##
## LEF for PtnCells ;
## created by Innovus v19.12-s087_1 on Tue Apr 28 21:20:15 2026
##

VERSION 5.8 ;

BUSBITCHARS "[]" ;
DIVIDERCHAR "/" ;

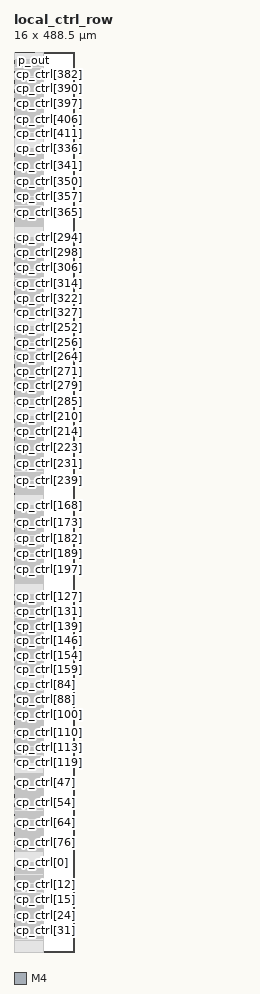
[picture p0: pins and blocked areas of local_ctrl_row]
MACRO local_ctrl_row
  CLASS BLOCK ;
  SIZE 16.000000 BY 488.500000 ;
  FOREIGN local_ctrl_row 0.000000 0.000000 ;
  ORIGIN 0 0 ;
  SYMMETRY X Y R90 ;
  PIN clk
    DIRECTION INPUT ;
    USE SIGNAL ;
    PORT
      LAYER M4 ;
        RECT 0.900000 488.300000 1.100000 488.500000 ;
    END
  END clk
  PIN rstn
    DIRECTION INPUT ;
    USE SIGNAL ;
    PORT
      LAYER M4 ;
        RECT 2.000000 488.300000 2.200000 488.500000 ;
    END
  END rstn
  PIN wr_vld
    DIRECTION INPUT ;
    USE SIGNAL ;
    PORT
      LAYER M4 ;
        RECT 4.200000 488.300000 4.400000 488.500000 ;
    END
  END wr_vld
  PIN wr_data_in
    DIRECTION INPUT ;
    USE SIGNAL ;
    PORT
      LAYER M4 ;
        RECT 3.100000 488.300000 3.300000 488.500000 ;
    END
  END wr_data_in
  PIN rd_rdy
    DIRECTION INPUT ;
    USE SIGNAL ;
    PORT
      LAYER M4 ;
        RECT 5.300000 488.300000 5.500000 488.500000 ;
    END
  END rd_rdy
  PIN p_code_vld
    DIRECTION INPUT ;
    USE SIGNAL ;
    PORT
      LAYER M4 ;
        RECT 8.600000 488.300000 8.800000 488.500000 ;
    END
  END p_code_vld
  PIN p_code[19]
    DIRECTION INPUT ;
    USE SIGNAL ;
    PORT
      LAYER M4 ;
        RECT 0.000000 449.120000 0.200000 449.320000 ;
    END
  END p_code[19]
  PIN p_code[18]
    DIRECTION INPUT ;
    USE SIGNAL ;
    PORT
      LAYER M4 ;
        RECT 0.000000 450.100000 0.200000 450.300000 ;
    END
  END p_code[18]
  PIN p_code[17]
    DIRECTION INPUT ;
    USE SIGNAL ;
    PORT
      LAYER M4 ;
        RECT 0.000000 400.670000 0.200000 400.870000 ;
    END
  END p_code[17]
  PIN p_code[16]
    DIRECTION INPUT ;
    USE SIGNAL ;
    PORT
      LAYER M4 ;
        RECT 0.000000 401.650000 0.200000 401.850000 ;
    END
  END p_code[16]
  PIN p_code[15]
    DIRECTION INPUT ;
    USE SIGNAL ;
    PORT
      LAYER M4 ;
        RECT 0.000000 352.220000 0.200000 352.420000 ;
    END
  END p_code[15]
  PIN p_code[14]
    DIRECTION INPUT ;
    USE SIGNAL ;
    PORT
      LAYER M4 ;
        RECT 0.000000 353.200000 0.200000 353.400000 ;
    END
  END p_code[14]
  PIN p_code[13]
    DIRECTION INPUT ;
    USE SIGNAL ;
    PORT
      LAYER M4 ;
        RECT 0.000000 303.770000 0.200000 303.970000 ;
    END
  END p_code[13]
  PIN p_code[12]
    DIRECTION INPUT ;
    USE SIGNAL ;
    PORT
      LAYER M4 ;
        RECT 0.000000 304.750000 0.200000 304.950000 ;
    END
  END p_code[12]
  PIN p_code[11]
    DIRECTION INPUT ;
    USE SIGNAL ;
    PORT
      LAYER M4 ;
        RECT 0.000000 255.320000 0.200000 255.520000 ;
    END
  END p_code[11]
  PIN p_code[10]
    DIRECTION INPUT ;
    USE SIGNAL ;
    PORT
      LAYER M4 ;
        RECT 0.000000 256.300000 0.200000 256.500000 ;
    END
  END p_code[10]
  PIN p_code[9]
    DIRECTION INPUT ;
    USE SIGNAL ;
    PORT
      LAYER M4 ;
        RECT 0.000000 206.870000 0.200000 207.070000 ;
    END
  END p_code[9]
  PIN p_code[8]
    DIRECTION INPUT ;
    USE SIGNAL ;
    PORT
      LAYER M4 ;
        RECT 0.000000 207.850000 0.200000 208.050000 ;
    END
  END p_code[8]
  PIN p_code[7]
    DIRECTION INPUT ;
    USE SIGNAL ;
    PORT
      LAYER M4 ;
        RECT 0.000000 158.420000 0.200000 158.620000 ;
    END
  END p_code[7]
  PIN p_code[6]
    DIRECTION INPUT ;
    USE SIGNAL ;
    PORT
      LAYER M4 ;
        RECT 0.000000 159.400000 0.200000 159.600000 ;
    END
  END p_code[6]
  PIN p_code[5]
    DIRECTION INPUT ;
    USE SIGNAL ;
    PORT
      LAYER M4 ;
        RECT 0.000000 109.970000 0.200000 110.170000 ;
    END
  END p_code[5]
  PIN p_code[4]
    DIRECTION INPUT ;
    USE SIGNAL ;
    PORT
      LAYER M4 ;
        RECT 0.000000 110.950000 0.200000 111.150000 ;
    END
  END p_code[4]
  PIN p_code[3]
    DIRECTION INPUT ;
    USE SIGNAL ;
    PORT
      LAYER M4 ;
        RECT 0.000000 61.520000 0.200000 61.720000 ;
    END
  END p_code[3]
  PIN p_code[2]
    DIRECTION INPUT ;
    USE SIGNAL ;
    PORT
      LAYER M4 ;
        RECT 0.000000 62.500000 0.200000 62.700000 ;
    END
  END p_code[2]
  PIN p_code[1]
    DIRECTION INPUT ;
    USE SIGNAL ;
    PORT
      LAYER M4 ;
        RECT 0.000000 13.070000 0.200000 13.270000 ;
    END
  END p_code[1]
  PIN p_code[0]
    DIRECTION INPUT ;
    USE SIGNAL ;
    PORT
      LAYER M4 ;
        RECT 0.000000 14.050000 0.200000 14.250000 ;
    END
  END p_code[0]
  PIN cp_ctrl[419]
    DIRECTION OUTPUT ;
    USE SIGNAL ;
    PORT
      LAYER M4 ;
        RECT 0.000000 455.000000 0.200000 455.200000 ;
    END
  END cp_ctrl[419]
  PIN cp_ctrl[418]
    DIRECTION OUTPUT ;
    USE SIGNAL ;
    PORT
      LAYER M4 ;
        RECT 0.000000 469.700000 0.200000 469.900000 ;
    END
  END cp_ctrl[418]
  PIN cp_ctrl[417]
    DIRECTION OUTPUT ;
    USE SIGNAL ;
    PORT
      LAYER M4 ;
        RECT 0.000000 442.260000 0.200000 442.460000 ;
    END
  END cp_ctrl[417]
  PIN cp_ctrl[416]
    DIRECTION OUTPUT ;
    USE SIGNAL ;
    PORT
      LAYER M4 ;
        RECT 0.000000 443.240000 0.200000 443.440000 ;
    END
  END cp_ctrl[416]
  PIN cp_ctrl[415]
    DIRECTION OUTPUT ;
    USE SIGNAL ;
    PORT
      LAYER M4 ;
        RECT 0.000000 444.220000 0.200000 444.420000 ;
    END
  END cp_ctrl[415]
  PIN cp_ctrl[414]
    DIRECTION OUTPUT ;
    USE SIGNAL ;
    PORT
      LAYER M4 ;
        RECT 0.000000 445.200000 0.200000 445.400000 ;
    END
  END cp_ctrl[414]
  PIN cp_ctrl[413]
    DIRECTION OUTPUT ;
    USE SIGNAL ;
    PORT
      LAYER M4 ;
        RECT 0.000000 446.180000 0.200000 446.380000 ;
    END
  END cp_ctrl[413]
  PIN cp_ctrl[412]
    DIRECTION OUTPUT ;
    USE SIGNAL ;
    PORT
      LAYER M4 ;
        RECT 0.000000 447.160000 0.200000 447.360000 ;
    END
  END cp_ctrl[412]
  PIN cp_ctrl[411]
    DIRECTION OUTPUT ;
    USE SIGNAL ;
    PORT
      LAYER M4 ;
        RECT 0.000000 448.140000 0.200000 448.340000 ;
    END
  END cp_ctrl[411]
  PIN cp_ctrl[410]
    DIRECTION OUTPUT ;
    USE SIGNAL ;
    PORT
      LAYER M4 ;
        RECT 0.000000 451.080000 0.200000 451.280000 ;
    END
  END cp_ctrl[410]
  PIN cp_ctrl[409]
    DIRECTION OUTPUT ;
    USE SIGNAL ;
    PORT
      LAYER M4 ;
        RECT 0.000000 452.060000 0.200000 452.260000 ;
    END
  END cp_ctrl[409]
  PIN cp_ctrl[408]
    DIRECTION OUTPUT ;
    USE SIGNAL ;
    PORT
      LAYER M4 ;
        RECT 0.000000 453.040000 0.200000 453.240000 ;
    END
  END cp_ctrl[408]
  PIN cp_ctrl[407]
    DIRECTION OUTPUT ;
    USE SIGNAL ;
    PORT
      LAYER M4 ;
        RECT 0.000000 454.020000 0.200000 454.220000 ;
    END
  END cp_ctrl[407]
  PIN cp_ctrl[406]
    DIRECTION OUTPUT ;
    USE SIGNAL ;
    PORT
      LAYER M4 ;
        RECT 0.000000 455.980000 0.200000 456.180000 ;
    END
  END cp_ctrl[406]
  PIN cp_ctrl[405]
    DIRECTION OUTPUT ;
    USE SIGNAL ;
    PORT
      LAYER M4 ;
        RECT 0.000000 456.960000 0.200000 457.160000 ;
    END
  END cp_ctrl[405]
  PIN cp_ctrl[404]
    DIRECTION OUTPUT ;
    USE SIGNAL ;
    PORT
      LAYER M4 ;
        RECT 0.000000 457.940000 0.200000 458.140000 ;
    END
  END cp_ctrl[404]
  PIN cp_ctrl[403]
    DIRECTION OUTPUT ;
    USE SIGNAL ;
    PORT
      LAYER M4 ;
        RECT 0.000000 458.920000 0.200000 459.120000 ;
    END
  END cp_ctrl[403]
  PIN cp_ctrl[402]
    DIRECTION OUTPUT ;
    USE SIGNAL ;
    PORT
      LAYER M4 ;
        RECT 0.000000 459.900000 0.200000 460.100000 ;
    END
  END cp_ctrl[402]
  PIN cp_ctrl[401]
    DIRECTION OUTPUT ;
    USE SIGNAL ;
    PORT
      LAYER M4 ;
        RECT 0.000000 460.880000 0.200000 461.080000 ;
    END
  END cp_ctrl[401]
  PIN cp_ctrl[400]
    DIRECTION OUTPUT ;
    USE SIGNAL ;
    PORT
      LAYER M4 ;
        RECT 0.000000 461.860000 0.200000 462.060000 ;
    END
  END cp_ctrl[400]
  PIN cp_ctrl[399]
    DIRECTION OUTPUT ;
    USE SIGNAL ;
    PORT
      LAYER M4 ;
        RECT 0.000000 462.840000 0.200000 463.040000 ;
    END
  END cp_ctrl[399]
  PIN cp_ctrl[398]
    DIRECTION OUTPUT ;
    USE SIGNAL ;
    PORT
      LAYER M4 ;
        RECT 0.000000 463.820000 0.200000 464.020000 ;
    END
  END cp_ctrl[398]
  PIN cp_ctrl[397]
    DIRECTION OUTPUT ;
    USE SIGNAL ;
    PORT
      LAYER M4 ;
        RECT 0.000000 464.800000 0.200000 465.000000 ;
    END
  END cp_ctrl[397]
  PIN cp_ctrl[396]
    DIRECTION OUTPUT ;
    USE SIGNAL ;
    PORT
      LAYER M4 ;
        RECT 0.000000 465.780000 0.200000 465.980000 ;
    END
  END cp_ctrl[396]
  PIN cp_ctrl[395]
    DIRECTION OUTPUT ;
    USE SIGNAL ;
    PORT
      LAYER M4 ;
        RECT 0.000000 466.760000 0.200000 466.960000 ;
    END
  END cp_ctrl[395]
  PIN cp_ctrl[394]
    DIRECTION OUTPUT ;
    USE SIGNAL ;
    PORT
      LAYER M4 ;
        RECT 0.000000 467.740000 0.200000 467.940000 ;
    END
  END cp_ctrl[394]
  PIN cp_ctrl[393]
    DIRECTION OUTPUT ;
    USE SIGNAL ;
    PORT
      LAYER M4 ;
        RECT 0.000000 468.720000 0.200000 468.920000 ;
    END
  END cp_ctrl[393]
  PIN cp_ctrl[392]
    DIRECTION OUTPUT ;
    USE SIGNAL ;
    PORT
      LAYER M4 ;
        RECT 0.000000 470.680000 0.200000 470.880000 ;
    END
  END cp_ctrl[392]
  PIN cp_ctrl[391]
    DIRECTION OUTPUT ;
    USE SIGNAL ;
    PORT
      LAYER M4 ;
        RECT 0.000000 471.660000 0.200000 471.860000 ;
    END
  END cp_ctrl[391]
  PIN cp_ctrl[390]
    DIRECTION OUTPUT ;
    USE SIGNAL ;
    PORT
      LAYER M4 ;
        RECT 0.000000 472.640000 0.200000 472.840000 ;
    END
  END cp_ctrl[390]
  PIN cp_ctrl[389]
    DIRECTION OUTPUT ;
    USE SIGNAL ;
    PORT
      LAYER M4 ;
        RECT 0.000000 473.620000 0.200000 473.820000 ;
    END
  END cp_ctrl[389]
  PIN cp_ctrl[388]
    DIRECTION OUTPUT ;
    USE SIGNAL ;
    PORT
      LAYER M4 ;
        RECT 0.000000 474.600000 0.200000 474.800000 ;
    END
  END cp_ctrl[388]
  PIN cp_ctrl[387]
    DIRECTION OUTPUT ;
    USE SIGNAL ;
    PORT
      LAYER M4 ;
        RECT 0.000000 475.580000 0.200000 475.780000 ;
    END
  END cp_ctrl[387]
  PIN cp_ctrl[386]
    DIRECTION OUTPUT ;
    USE SIGNAL ;
    PORT
      LAYER M4 ;
        RECT 0.000000 476.560000 0.200000 476.760000 ;
    END
  END cp_ctrl[386]
  PIN cp_ctrl[385]
    DIRECTION OUTPUT ;
    USE SIGNAL ;
    PORT
      LAYER M4 ;
        RECT 0.000000 477.540000 0.200000 477.740000 ;
    END
  END cp_ctrl[385]
  PIN cp_ctrl[384]
    DIRECTION OUTPUT ;
    USE SIGNAL ;
    PORT
      LAYER M4 ;
        RECT 0.000000 478.520000 0.200000 478.720000 ;
    END
  END cp_ctrl[384]
  PIN cp_ctrl[383]
    DIRECTION OUTPUT ;
    USE SIGNAL ;
    PORT
      LAYER M4 ;
        RECT 0.000000 479.500000 0.200000 479.700000 ;
    END
  END cp_ctrl[383]
  PIN cp_ctrl[382]
    DIRECTION OUTPUT ;
    USE SIGNAL ;
    PORT
      LAYER M4 ;
        RECT 0.000000 480.480000 0.200000 480.680000 ;
    END
  END cp_ctrl[382]
  PIN cp_ctrl[381]
    DIRECTION OUTPUT ;
    USE SIGNAL ;
    PORT
      LAYER M4 ;
        RECT 0.000000 481.460000 0.200000 481.660000 ;
    END
  END cp_ctrl[381]
  PIN cp_ctrl[380]
    DIRECTION OUTPUT ;
    USE SIGNAL ;
    PORT
      LAYER M4 ;
        RECT 0.000000 482.440000 0.200000 482.640000 ;
    END
  END cp_ctrl[380]
  PIN cp_ctrl[379]
    DIRECTION OUTPUT ;
    USE SIGNAL ;
    PORT
      LAYER M4 ;
        RECT 0.000000 483.420000 0.200000 483.620000 ;
    END
  END cp_ctrl[379]
  PIN cp_ctrl[378]
    DIRECTION OUTPUT ;
    USE SIGNAL ;
    PORT
      LAYER M4 ;
        RECT 0.000000 484.400000 0.200000 484.600000 ;
    END
  END cp_ctrl[378]
  PIN cp_ctrl[377]
    DIRECTION OUTPUT ;
    USE SIGNAL ;
    PORT
      LAYER M4 ;
        RECT 0.000000 406.550000 0.200000 406.750000 ;
    END
  END cp_ctrl[377]
  PIN cp_ctrl[376]
    DIRECTION OUTPUT ;
    USE SIGNAL ;
    PORT
      LAYER M4 ;
        RECT 0.000000 421.250000 0.200000 421.450000 ;
    END
  END cp_ctrl[376]
  PIN cp_ctrl[375]
    DIRECTION OUTPUT ;
    USE SIGNAL ;
    PORT
      LAYER M4 ;
        RECT 0.000000 393.810000 0.200000 394.010000 ;
    END
  END cp_ctrl[375]
  PIN cp_ctrl[374]
    DIRECTION OUTPUT ;
    USE SIGNAL ;
    PORT
      LAYER M4 ;
        RECT 0.000000 394.790000 0.200000 394.990000 ;
    END
  END cp_ctrl[374]
  PIN cp_ctrl[373]
    DIRECTION OUTPUT ;
    USE SIGNAL ;
    PORT
      LAYER M4 ;
        RECT 0.000000 395.770000 0.200000 395.970000 ;
    END
  END cp_ctrl[373]
  PIN cp_ctrl[372]
    DIRECTION OUTPUT ;
    USE SIGNAL ;
    PORT
      LAYER M4 ;
        RECT 0.000000 396.750000 0.200000 396.950000 ;
    END
  END cp_ctrl[372]
  PIN cp_ctrl[371]
    DIRECTION OUTPUT ;
    USE SIGNAL ;
    PORT
      LAYER M4 ;
        RECT 0.000000 397.730000 0.200000 397.930000 ;
    END
  END cp_ctrl[371]
  PIN cp_ctrl[370]
    DIRECTION OUTPUT ;
    USE SIGNAL ;
    PORT
      LAYER M4 ;
        RECT 0.000000 398.710000 0.200000 398.910000 ;
    END
  END cp_ctrl[370]
  PIN cp_ctrl[369]
    DIRECTION OUTPUT ;
    USE SIGNAL ;
    PORT
      LAYER M4 ;
        RECT 0.000000 399.690000 0.200000 399.890000 ;
    END
  END cp_ctrl[369]
  PIN cp_ctrl[368]
    DIRECTION OUTPUT ;
    USE SIGNAL ;
    PORT
      LAYER M4 ;
        RECT 0.000000 402.630000 0.200000 402.830000 ;
    END
  END cp_ctrl[368]
  PIN cp_ctrl[367]
    DIRECTION OUTPUT ;
    USE SIGNAL ;
    PORT
      LAYER M4 ;
        RECT 0.000000 403.610000 0.200000 403.810000 ;
    END
  END cp_ctrl[367]
  PIN cp_ctrl[366]
    DIRECTION OUTPUT ;
    USE SIGNAL ;
    PORT
      LAYER M4 ;
        RECT 0.000000 404.590000 0.200000 404.790000 ;
    END
  END cp_ctrl[366]
  PIN cp_ctrl[365]
    DIRECTION OUTPUT ;
    USE SIGNAL ;
    PORT
      LAYER M4 ;
        RECT 0.000000 405.570000 0.200000 405.770000 ;
    END
  END cp_ctrl[365]
  PIN cp_ctrl[364]
    DIRECTION OUTPUT ;
    USE SIGNAL ;
    PORT
      LAYER M4 ;
        RECT 0.000000 407.530000 0.200000 407.730000 ;
    END
  END cp_ctrl[364]
  PIN cp_ctrl[363]
    DIRECTION OUTPUT ;
    USE SIGNAL ;
    PORT
      LAYER M4 ;
        RECT 0.000000 408.510000 0.200000 408.710000 ;
    END
  END cp_ctrl[363]
  PIN cp_ctrl[362]
    DIRECTION OUTPUT ;
    USE SIGNAL ;
    PORT
      LAYER M4 ;
        RECT 0.000000 409.490000 0.200000 409.690000 ;
    END
  END cp_ctrl[362]
  PIN cp_ctrl[361]
    DIRECTION OUTPUT ;
    USE SIGNAL ;
    PORT
      LAYER M4 ;
        RECT 0.000000 410.470000 0.200000 410.670000 ;
    END
  END cp_ctrl[361]
  PIN cp_ctrl[360]
    DIRECTION OUTPUT ;
    USE SIGNAL ;
    PORT
      LAYER M4 ;
        RECT 0.000000 411.450000 0.200000 411.650000 ;
    END
  END cp_ctrl[360]
  PIN cp_ctrl[359]
    DIRECTION OUTPUT ;
    USE SIGNAL ;
    PORT
      LAYER M4 ;
        RECT 0.000000 412.430000 0.200000 412.630000 ;
    END
  END cp_ctrl[359]
  PIN cp_ctrl[358]
    DIRECTION OUTPUT ;
    USE SIGNAL ;
    PORT
      LAYER M4 ;
        RECT 0.000000 413.410000 0.200000 413.610000 ;
    END
  END cp_ctrl[358]
  PIN cp_ctrl[357]
    DIRECTION OUTPUT ;
    USE SIGNAL ;
    PORT
      LAYER M4 ;
        RECT 0.000000 414.390000 0.200000 414.590000 ;
    END
  END cp_ctrl[357]
  PIN cp_ctrl[356]
    DIRECTION OUTPUT ;
    USE SIGNAL ;
    PORT
      LAYER M4 ;
        RECT 0.000000 415.370000 0.200000 415.570000 ;
    END
  END cp_ctrl[356]
  PIN cp_ctrl[355]
    DIRECTION OUTPUT ;
    USE SIGNAL ;
    PORT
      LAYER M4 ;
        RECT 0.000000 416.350000 0.200000 416.550000 ;
    END
  END cp_ctrl[355]
  PIN cp_ctrl[354]
    DIRECTION OUTPUT ;
    USE SIGNAL ;
    PORT
      LAYER M4 ;
        RECT 0.000000 417.330000 0.200000 417.530000 ;
    END
  END cp_ctrl[354]
  PIN cp_ctrl[353]
    DIRECTION OUTPUT ;
    USE SIGNAL ;
    PORT
      LAYER M4 ;
        RECT 0.000000 418.310000 0.200000 418.510000 ;
    END
  END cp_ctrl[353]
  PIN cp_ctrl[352]
    DIRECTION OUTPUT ;
    USE SIGNAL ;
    PORT
      LAYER M4 ;
        RECT 0.000000 419.290000 0.200000 419.490000 ;
    END
  END cp_ctrl[352]
  PIN cp_ctrl[351]
    DIRECTION OUTPUT ;
    USE SIGNAL ;
    PORT
      LAYER M4 ;
        RECT 0.000000 420.270000 0.200000 420.470000 ;
    END
  END cp_ctrl[351]
  PIN cp_ctrl[350]
    DIRECTION OUTPUT ;
    USE SIGNAL ;
    PORT
      LAYER M4 ;
        RECT 0.000000 422.230000 0.200000 422.430000 ;
    END
  END cp_ctrl[350]
  PIN cp_ctrl[349]
    DIRECTION OUTPUT ;
    USE SIGNAL ;
    PORT
      LAYER M4 ;
        RECT 0.000000 423.210000 0.200000 423.410000 ;
    END
  END cp_ctrl[349]
  PIN cp_ctrl[348]
    DIRECTION OUTPUT ;
    USE SIGNAL ;
    PORT
      LAYER M4 ;
        RECT 0.000000 424.190000 0.200000 424.390000 ;
    END
  END cp_ctrl[348]
  PIN cp_ctrl[347]
    DIRECTION OUTPUT ;
    USE SIGNAL ;
    PORT
      LAYER M4 ;
        RECT 0.000000 425.170000 0.200000 425.370000 ;
    END
  END cp_ctrl[347]
  PIN cp_ctrl[346]
    DIRECTION OUTPUT ;
    USE SIGNAL ;
    PORT
      LAYER M4 ;
        RECT 0.000000 426.150000 0.200000 426.350000 ;
    END
  END cp_ctrl[346]
  PIN cp_ctrl[345]
    DIRECTION OUTPUT ;
    USE SIGNAL ;
    PORT
      LAYER M4 ;
        RECT 0.000000 427.130000 0.200000 427.330000 ;
    END
  END cp_ctrl[345]
  PIN cp_ctrl[344]
    DIRECTION OUTPUT ;
    USE SIGNAL ;
    PORT
      LAYER M4 ;
        RECT 0.000000 428.110000 0.200000 428.310000 ;
    END
  END cp_ctrl[344]
  PIN cp_ctrl[343]
    DIRECTION OUTPUT ;
    USE SIGNAL ;
    PORT
      LAYER M4 ;
        RECT 0.000000 429.090000 0.200000 429.290000 ;
    END
  END cp_ctrl[343]
  PIN cp_ctrl[342]
    DIRECTION OUTPUT ;
    USE SIGNAL ;
    PORT
      LAYER M4 ;
        RECT 0.000000 430.070000 0.200000 430.270000 ;
    END
  END cp_ctrl[342]
  PIN cp_ctrl[341]
    DIRECTION OUTPUT ;
    USE SIGNAL ;
    PORT
      LAYER M4 ;
        RECT 0.000000 431.050000 0.200000 431.250000 ;
    END
  END cp_ctrl[341]
  PIN cp_ctrl[340]
    DIRECTION OUTPUT ;
    USE SIGNAL ;
    PORT
      LAYER M4 ;
        RECT 0.000000 432.030000 0.200000 432.230000 ;
    END
  END cp_ctrl[340]
  PIN cp_ctrl[339]
    DIRECTION OUTPUT ;
    USE SIGNAL ;
    PORT
      LAYER M4 ;
        RECT 0.000000 433.010000 0.200000 433.210000 ;
    END
  END cp_ctrl[339]
  PIN cp_ctrl[338]
    DIRECTION OUTPUT ;
    USE SIGNAL ;
    PORT
      LAYER M4 ;
        RECT 0.000000 433.990000 0.200000 434.190000 ;
    END
  END cp_ctrl[338]
  PIN cp_ctrl[337]
    DIRECTION OUTPUT ;
    USE SIGNAL ;
    PORT
      LAYER M4 ;
        RECT 0.000000 434.970000 0.200000 435.170000 ;
    END
  END cp_ctrl[337]
  PIN cp_ctrl[336]
    DIRECTION OUTPUT ;
    USE SIGNAL ;
    PORT
      LAYER M4 ;
        RECT 0.000000 435.950000 0.200000 436.150000 ;
    END
  END cp_ctrl[336]
  PIN cp_ctrl[335]
    DIRECTION OUTPUT ;
    USE SIGNAL ;
    PORT
      LAYER M4 ;
        RECT 0.000000 358.100000 0.200000 358.300000 ;
    END
  END cp_ctrl[335]
  PIN cp_ctrl[334]
    DIRECTION OUTPUT ;
    USE SIGNAL ;
    PORT
      LAYER M4 ;
        RECT 0.000000 372.800000 0.200000 373.000000 ;
    END
  END cp_ctrl[334]
  PIN cp_ctrl[333]
    DIRECTION OUTPUT ;
    USE SIGNAL ;
    PORT
      LAYER M4 ;
        RECT 0.000000 345.360000 0.200000 345.560000 ;
    END
  END cp_ctrl[333]
  PIN cp_ctrl[332]
    DIRECTION OUTPUT ;
    USE SIGNAL ;
    PORT
      LAYER M4 ;
        RECT 0.000000 346.340000 0.200000 346.540000 ;
    END
  END cp_ctrl[332]
  PIN cp_ctrl[331]
    DIRECTION OUTPUT ;
    USE SIGNAL ;
    PORT
      LAYER M4 ;
        RECT 0.000000 347.320000 0.200000 347.520000 ;
    END
  END cp_ctrl[331]
  PIN cp_ctrl[330]
    DIRECTION OUTPUT ;
    USE SIGNAL ;
    PORT
      LAYER M4 ;
        RECT 0.000000 348.300000 0.200000 348.500000 ;
    END
  END cp_ctrl[330]
  PIN cp_ctrl[329]
    DIRECTION OUTPUT ;
    USE SIGNAL ;
    PORT
      LAYER M4 ;
        RECT 0.000000 349.280000 0.200000 349.480000 ;
    END
  END cp_ctrl[329]
  PIN cp_ctrl[328]
    DIRECTION OUTPUT ;
    USE SIGNAL ;
    PORT
      LAYER M4 ;
        RECT 0.000000 350.260000 0.200000 350.460000 ;
    END
  END cp_ctrl[328]
  PIN cp_ctrl[327]
    DIRECTION OUTPUT ;
    USE SIGNAL ;
    PORT
      LAYER M4 ;
        RECT 0.000000 351.240000 0.200000 351.440000 ;
    END
  END cp_ctrl[327]
  PIN cp_ctrl[326]
    DIRECTION OUTPUT ;
    USE SIGNAL ;
    PORT
      LAYER M4 ;
        RECT 0.000000 354.180000 0.200000 354.380000 ;
    END
  END cp_ctrl[326]
  PIN cp_ctrl[325]
    DIRECTION OUTPUT ;
    USE SIGNAL ;
    PORT
      LAYER M4 ;
        RECT 0.000000 355.160000 0.200000 355.360000 ;
    END
  END cp_ctrl[325]
  PIN cp_ctrl[324]
    DIRECTION OUTPUT ;
    USE SIGNAL ;
    PORT
      LAYER M4 ;
        RECT 0.000000 356.140000 0.200000 356.340000 ;
    END
  END cp_ctrl[324]
  PIN cp_ctrl[323]
    DIRECTION OUTPUT ;
    USE SIGNAL ;
    PORT
      LAYER M4 ;
        RECT 0.000000 357.120000 0.200000 357.320000 ;
    END
  END cp_ctrl[323]
  PIN cp_ctrl[322]
    DIRECTION OUTPUT ;
    USE SIGNAL ;
    PORT
      LAYER M4 ;
        RECT 0.000000 359.080000 0.200000 359.280000 ;
    END
  END cp_ctrl[322]
  PIN cp_ctrl[321]
    DIRECTION OUTPUT ;
    USE SIGNAL ;
    PORT
      LAYER M4 ;
        RECT 0.000000 360.060000 0.200000 360.260000 ;
    END
  END cp_ctrl[321]
  PIN cp_ctrl[320]
    DIRECTION OUTPUT ;
    USE SIGNAL ;
    PORT
      LAYER M4 ;
        RECT 0.000000 361.040000 0.200000 361.240000 ;
    END
  END cp_ctrl[320]
  PIN cp_ctrl[319]
    DIRECTION OUTPUT ;
    USE SIGNAL ;
    PORT
      LAYER M4 ;
        RECT 0.000000 362.020000 0.200000 362.220000 ;
    END
  END cp_ctrl[319]
  PIN cp_ctrl[318]
    DIRECTION OUTPUT ;
    USE SIGNAL ;
    PORT
      LAYER M4 ;
        RECT 0.000000 363.000000 0.200000 363.200000 ;
    END
  END cp_ctrl[318]
  PIN cp_ctrl[317]
    DIRECTION OUTPUT ;
    USE SIGNAL ;
    PORT
      LAYER M4 ;
        RECT 0.000000 363.980000 0.200000 364.180000 ;
    END
  END cp_ctrl[317]
  PIN cp_ctrl[316]
    DIRECTION OUTPUT ;
    USE SIGNAL ;
    PORT
      LAYER M4 ;
        RECT 0.000000 364.960000 0.200000 365.160000 ;
    END
  END cp_ctrl[316]
  PIN cp_ctrl[315]
    DIRECTION OUTPUT ;
    USE SIGNAL ;
    PORT
      LAYER M4 ;
        RECT 0.000000 365.940000 0.200000 366.140000 ;
    END
  END cp_ctrl[315]
  PIN cp_ctrl[314]
    DIRECTION OUTPUT ;
    USE SIGNAL ;
    PORT
      LAYER M4 ;
        RECT 0.000000 366.920000 0.200000 367.120000 ;
    END
  END cp_ctrl[314]
  PIN cp_ctrl[313]
    DIRECTION OUTPUT ;
    USE SIGNAL ;
    PORT
      LAYER M4 ;
        RECT 0.000000 367.900000 0.200000 368.100000 ;
    END
  END cp_ctrl[313]
  PIN cp_ctrl[312]
    DIRECTION OUTPUT ;
    USE SIGNAL ;
    PORT
      LAYER M4 ;
        RECT 0.000000 368.880000 0.200000 369.080000 ;
    END
  END cp_ctrl[312]
  PIN cp_ctrl[311]
    DIRECTION OUTPUT ;
    USE SIGNAL ;
    PORT
      LAYER M4 ;
        RECT 0.000000 369.860000 0.200000 370.060000 ;
    END
  END cp_ctrl[311]
  PIN cp_ctrl[310]
    DIRECTION OUTPUT ;
    USE SIGNAL ;
    PORT
      LAYER M4 ;
        RECT 0.000000 370.840000 0.200000 371.040000 ;
    END
  END cp_ctrl[310]
  PIN cp_ctrl[309]
    DIRECTION OUTPUT ;
    USE SIGNAL ;
    PORT
      LAYER M4 ;
        RECT 0.000000 371.820000 0.200000 372.020000 ;
    END
  END cp_ctrl[309]
  PIN cp_ctrl[308]
    DIRECTION OUTPUT ;
    USE SIGNAL ;
    PORT
      LAYER M4 ;
        RECT 0.000000 373.780000 0.200000 373.980000 ;
    END
  END cp_ctrl[308]
  PIN cp_ctrl[307]
    DIRECTION OUTPUT ;
    USE SIGNAL ;
    PORT
      LAYER M4 ;
        RECT 0.000000 374.760000 0.200000 374.960000 ;
    END
  END cp_ctrl[307]
  PIN cp_ctrl[306]
    DIRECTION OUTPUT ;
    USE SIGNAL ;
    PORT
      LAYER M4 ;
        RECT 0.000000 375.740000 0.200000 375.940000 ;
    END
  END cp_ctrl[306]
  PIN cp_ctrl[305]
    DIRECTION OUTPUT ;
    USE SIGNAL ;
    PORT
      LAYER M4 ;
        RECT 0.000000 376.720000 0.200000 376.920000 ;
    END
  END cp_ctrl[305]
  PIN cp_ctrl[304]
    DIRECTION OUTPUT ;
    USE SIGNAL ;
    PORT
      LAYER M4 ;
        RECT 0.000000 377.700000 0.200000 377.900000 ;
    END
  END cp_ctrl[304]
  PIN cp_ctrl[303]
    DIRECTION OUTPUT ;
    USE SIGNAL ;
    PORT
      LAYER M4 ;
        RECT 0.000000 378.680000 0.200000 378.880000 ;
    END
  END cp_ctrl[303]
  PIN cp_ctrl[302]
    DIRECTION OUTPUT ;
    USE SIGNAL ;
    PORT
      LAYER M4 ;
        RECT 0.000000 379.660000 0.200000 379.860000 ;
    END
  END cp_ctrl[302]
  PIN cp_ctrl[301]
    DIRECTION OUTPUT ;
    USE SIGNAL ;
    PORT
      LAYER M4 ;
        RECT 0.000000 380.640000 0.200000 380.840000 ;
    END
  END cp_ctrl[301]
  PIN cp_ctrl[300]
    DIRECTION OUTPUT ;
    USE SIGNAL ;
    PORT
      LAYER M4 ;
        RECT 0.000000 381.620000 0.200000 381.820000 ;
    END
  END cp_ctrl[300]
  PIN cp_ctrl[299]
    DIRECTION OUTPUT ;
    USE SIGNAL ;
    PORT
      LAYER M4 ;
        RECT 0.000000 382.600000 0.200000 382.800000 ;
    END
  END cp_ctrl[299]
  PIN cp_ctrl[298]
    DIRECTION OUTPUT ;
    USE SIGNAL ;
    PORT
      LAYER M4 ;
        RECT 0.000000 383.580000 0.200000 383.780000 ;
    END
  END cp_ctrl[298]
  PIN cp_ctrl[297]
    DIRECTION OUTPUT ;
    USE SIGNAL ;
    PORT
      LAYER M4 ;
        RECT 0.000000 384.560000 0.200000 384.760000 ;
    END
  END cp_ctrl[297]
  PIN cp_ctrl[296]
    DIRECTION OUTPUT ;
    USE SIGNAL ;
    PORT
      LAYER M4 ;
        RECT 0.000000 385.540000 0.200000 385.740000 ;
    END
  END cp_ctrl[296]
  PIN cp_ctrl[295]
    DIRECTION OUTPUT ;
    USE SIGNAL ;
    PORT
      LAYER M4 ;
        RECT 0.000000 386.520000 0.200000 386.720000 ;
    END
  END cp_ctrl[295]
  PIN cp_ctrl[294]
    DIRECTION OUTPUT ;
    USE SIGNAL ;
    PORT
      LAYER M4 ;
        RECT 0.000000 387.500000 0.200000 387.700000 ;
    END
  END cp_ctrl[294]
  PIN cp_ctrl[293]
    DIRECTION OUTPUT ;
    USE SIGNAL ;
    PORT
      LAYER M4 ;
        RECT 0.000000 309.650000 0.200000 309.850000 ;
    END
  END cp_ctrl[293]
  PIN cp_ctrl[292]
    DIRECTION OUTPUT ;
    USE SIGNAL ;
    PORT
      LAYER M4 ;
        RECT 0.000000 324.350000 0.200000 324.550000 ;
    END
  END cp_ctrl[292]
  PIN cp_ctrl[291]
    DIRECTION OUTPUT ;
    USE SIGNAL ;
    PORT
      LAYER M4 ;
        RECT 0.000000 296.910000 0.200000 297.110000 ;
    END
  END cp_ctrl[291]
  PIN cp_ctrl[290]
    DIRECTION OUTPUT ;
    USE SIGNAL ;
    PORT
      LAYER M4 ;
        RECT 0.000000 297.890000 0.200000 298.090000 ;
    END
  END cp_ctrl[290]
  PIN cp_ctrl[289]
    DIRECTION OUTPUT ;
    USE SIGNAL ;
    PORT
      LAYER M4 ;
        RECT 0.000000 298.870000 0.200000 299.070000 ;
    END
  END cp_ctrl[289]
  PIN cp_ctrl[288]
    DIRECTION OUTPUT ;
    USE SIGNAL ;
    PORT
      LAYER M4 ;
        RECT 0.000000 299.850000 0.200000 300.050000 ;
    END
  END cp_ctrl[288]
  PIN cp_ctrl[287]
    DIRECTION OUTPUT ;
    USE SIGNAL ;
    PORT
      LAYER M4 ;
        RECT 0.000000 300.830000 0.200000 301.030000 ;
    END
  END cp_ctrl[287]
  PIN cp_ctrl[286]
    DIRECTION OUTPUT ;
    USE SIGNAL ;
    PORT
      LAYER M4 ;
        RECT 0.000000 301.810000 0.200000 302.010000 ;
    END
  END cp_ctrl[286]
  PIN cp_ctrl[285]
    DIRECTION OUTPUT ;
    USE SIGNAL ;
    PORT
      LAYER M4 ;
        RECT 0.000000 302.790000 0.200000 302.990000 ;
    END
  END cp_ctrl[285]
  PIN cp_ctrl[284]
    DIRECTION OUTPUT ;
    USE SIGNAL ;
    PORT
      LAYER M4 ;
        RECT 0.000000 305.730000 0.200000 305.930000 ;
    END
  END cp_ctrl[284]
  PIN cp_ctrl[283]
    DIRECTION OUTPUT ;
    USE SIGNAL ;
    PORT
      LAYER M4 ;
        RECT 0.000000 306.710000 0.200000 306.910000 ;
    END
  END cp_ctrl[283]
  PIN cp_ctrl[282]
    DIRECTION OUTPUT ;
    USE SIGNAL ;
    PORT
      LAYER M4 ;
        RECT 0.000000 307.690000 0.200000 307.890000 ;
    END
  END cp_ctrl[282]
  PIN cp_ctrl[281]
    DIRECTION OUTPUT ;
    USE SIGNAL ;
    PORT
      LAYER M4 ;
        RECT 0.000000 308.670000 0.200000 308.870000 ;
    END
  END cp_ctrl[281]
  PIN cp_ctrl[280]
    DIRECTION OUTPUT ;
    USE SIGNAL ;
    PORT
      LAYER M4 ;
        RECT 0.000000 310.630000 0.200000 310.830000 ;
    END
  END cp_ctrl[280]
  PIN cp_ctrl[279]
    DIRECTION OUTPUT ;
    USE SIGNAL ;
    PORT
      LAYER M4 ;
        RECT 0.000000 311.610000 0.200000 311.810000 ;
    END
  END cp_ctrl[279]
  PIN cp_ctrl[278]
    DIRECTION OUTPUT ;
    USE SIGNAL ;
    PORT
      LAYER M4 ;
        RECT 0.000000 312.590000 0.200000 312.790000 ;
    END
  END cp_ctrl[278]
  PIN cp_ctrl[277]
    DIRECTION OUTPUT ;
    USE SIGNAL ;
    PORT
      LAYER M4 ;
        RECT 0.000000 313.570000 0.200000 313.770000 ;
    END
  END cp_ctrl[277]
  PIN cp_ctrl[276]
    DIRECTION OUTPUT ;
    USE SIGNAL ;
    PORT
      LAYER M4 ;
        RECT 0.000000 314.550000 0.200000 314.750000 ;
    END
  END cp_ctrl[276]
  PIN cp_ctrl[275]
    DIRECTION OUTPUT ;
    USE SIGNAL ;
    PORT
      LAYER M4 ;
        RECT 0.000000 315.530000 0.200000 315.730000 ;
    END
  END cp_ctrl[275]
  PIN cp_ctrl[274]
    DIRECTION OUTPUT ;
    USE SIGNAL ;
    PORT
      LAYER M4 ;
        RECT 0.000000 316.510000 0.200000 316.710000 ;
    END
  END cp_ctrl[274]
  PIN cp_ctrl[273]
    DIRECTION OUTPUT ;
    USE SIGNAL ;
    PORT
      LAYER M4 ;
        RECT 0.000000 317.490000 0.200000 317.690000 ;
    END
  END cp_ctrl[273]
  PIN cp_ctrl[272]
    DIRECTION OUTPUT ;
    USE SIGNAL ;
    PORT
      LAYER M4 ;
        RECT 0.000000 318.470000 0.200000 318.670000 ;
    END
  END cp_ctrl[272]
  PIN cp_ctrl[271]
    DIRECTION OUTPUT ;
    USE SIGNAL ;
    PORT
      LAYER M4 ;
        RECT 0.000000 319.450000 0.200000 319.650000 ;
    END
  END cp_ctrl[271]
  PIN cp_ctrl[270]
    DIRECTION OUTPUT ;
    USE SIGNAL ;
    PORT
      LAYER M4 ;
        RECT 0.000000 320.430000 0.200000 320.630000 ;
    END
  END cp_ctrl[270]
  PIN cp_ctrl[269]
    DIRECTION OUTPUT ;
    USE SIGNAL ;
    PORT
      LAYER M4 ;
        RECT 0.000000 321.410000 0.200000 321.610000 ;
    END
  END cp_ctrl[269]
  PIN cp_ctrl[268]
    DIRECTION OUTPUT ;
    USE SIGNAL ;
    PORT
      LAYER M4 ;
        RECT 0.000000 322.390000 0.200000 322.590000 ;
    END
  END cp_ctrl[268]
  PIN cp_ctrl[267]
    DIRECTION OUTPUT ;
    USE SIGNAL ;
    PORT
      LAYER M4 ;
        RECT 0.000000 323.370000 0.200000 323.570000 ;
    END
  END cp_ctrl[267]
  PIN cp_ctrl[266]
    DIRECTION OUTPUT ;
    USE SIGNAL ;
    PORT
      LAYER M4 ;
        RECT 0.000000 325.330000 0.200000 325.530000 ;
    END
  END cp_ctrl[266]
  PIN cp_ctrl[265]
    DIRECTION OUTPUT ;
    USE SIGNAL ;
    PORT
      LAYER M4 ;
        RECT 0.000000 326.310000 0.200000 326.510000 ;
    END
  END cp_ctrl[265]
  PIN cp_ctrl[264]
    DIRECTION OUTPUT ;
    USE SIGNAL ;
    PORT
      LAYER M4 ;
        RECT 0.000000 327.290000 0.200000 327.490000 ;
    END
  END cp_ctrl[264]
  PIN cp_ctrl[263]
    DIRECTION OUTPUT ;
    USE SIGNAL ;
    PORT
      LAYER M4 ;
        RECT 0.000000 328.270000 0.200000 328.470000 ;
    END
  END cp_ctrl[263]
  PIN cp_ctrl[262]
    DIRECTION OUTPUT ;
    USE SIGNAL ;
    PORT
      LAYER M4 ;
        RECT 0.000000 329.250000 0.200000 329.450000 ;
    END
  END cp_ctrl[262]
  PIN cp_ctrl[261]
    DIRECTION OUTPUT ;
    USE SIGNAL ;
    PORT
      LAYER M4 ;
        RECT 0.000000 330.230000 0.200000 330.430000 ;
    END
  END cp_ctrl[261]
  PIN cp_ctrl[260]
    DIRECTION OUTPUT ;
    USE SIGNAL ;
    PORT
      LAYER M4 ;
        RECT 0.000000 331.210000 0.200000 331.410000 ;
    END
  END cp_ctrl[260]
  PIN cp_ctrl[259]
    DIRECTION OUTPUT ;
    USE SIGNAL ;
    PORT
      LAYER M4 ;
        RECT 0.000000 332.190000 0.200000 332.390000 ;
    END
  END cp_ctrl[259]
  PIN cp_ctrl[258]
    DIRECTION OUTPUT ;
    USE SIGNAL ;
    PORT
      LAYER M4 ;
        RECT 0.000000 333.170000 0.200000 333.370000 ;
    END
  END cp_ctrl[258]
  PIN cp_ctrl[257]
    DIRECTION OUTPUT ;
    USE SIGNAL ;
    PORT
      LAYER M4 ;
        RECT 0.000000 334.150000 0.200000 334.350000 ;
    END
  END cp_ctrl[257]
  PIN cp_ctrl[256]
    DIRECTION OUTPUT ;
    USE SIGNAL ;
    PORT
      LAYER M4 ;
        RECT 0.000000 335.130000 0.200000 335.330000 ;
    END
  END cp_ctrl[256]
  PIN cp_ctrl[255]
    DIRECTION OUTPUT ;
    USE SIGNAL ;
    PORT
      LAYER M4 ;
        RECT 0.000000 336.110000 0.200000 336.310000 ;
    END
  END cp_ctrl[255]
  PIN cp_ctrl[254]
    DIRECTION OUTPUT ;
    USE SIGNAL ;
    PORT
      LAYER M4 ;
        RECT 0.000000 337.090000 0.200000 337.290000 ;
    END
  END cp_ctrl[254]
  PIN cp_ctrl[253]
    DIRECTION OUTPUT ;
    USE SIGNAL ;
    PORT
      LAYER M4 ;
        RECT 0.000000 338.070000 0.200000 338.270000 ;
    END
  END cp_ctrl[253]
  PIN cp_ctrl[252]
    DIRECTION OUTPUT ;
    USE SIGNAL ;
    PORT
      LAYER M4 ;
        RECT 0.000000 339.050000 0.200000 339.250000 ;
    END
  END cp_ctrl[252]
  PIN cp_ctrl[251]
    DIRECTION OUTPUT ;
    USE SIGNAL ;
    PORT
      LAYER M4 ;
        RECT 0.000000 261.200000 0.200000 261.400000 ;
    END
  END cp_ctrl[251]
  PIN cp_ctrl[250]
    DIRECTION OUTPUT ;
    USE SIGNAL ;
    PORT
      LAYER M4 ;
        RECT 0.000000 275.900000 0.200000 276.100000 ;
    END
  END cp_ctrl[250]
  PIN cp_ctrl[249]
    DIRECTION OUTPUT ;
    USE SIGNAL ;
    PORT
      LAYER M4 ;
        RECT 0.000000 248.460000 0.200000 248.660000 ;
    END
  END cp_ctrl[249]
  PIN cp_ctrl[248]
    DIRECTION OUTPUT ;
    USE SIGNAL ;
    PORT
      LAYER M4 ;
        RECT 0.000000 249.440000 0.200000 249.640000 ;
    END
  END cp_ctrl[248]
  PIN cp_ctrl[247]
    DIRECTION OUTPUT ;
    USE SIGNAL ;
    PORT
      LAYER M4 ;
        RECT 0.000000 250.420000 0.200000 250.620000 ;
    END
  END cp_ctrl[247]
  PIN cp_ctrl[246]
    DIRECTION OUTPUT ;
    USE SIGNAL ;
    PORT
      LAYER M4 ;
        RECT 0.000000 251.400000 0.200000 251.600000 ;
    END
  END cp_ctrl[246]
  PIN cp_ctrl[245]
    DIRECTION OUTPUT ;
    USE SIGNAL ;
    PORT
      LAYER M4 ;
        RECT 0.000000 252.380000 0.200000 252.580000 ;
    END
  END cp_ctrl[245]
  PIN cp_ctrl[244]
    DIRECTION OUTPUT ;
    USE SIGNAL ;
    PORT
      LAYER M4 ;
        RECT 0.000000 253.360000 0.200000 253.560000 ;
    END
  END cp_ctrl[244]
  PIN cp_ctrl[243]
    DIRECTION OUTPUT ;
    USE SIGNAL ;
    PORT
      LAYER M4 ;
        RECT 0.000000 254.340000 0.200000 254.540000 ;
    END
  END cp_ctrl[243]
  PIN cp_ctrl[242]
    DIRECTION OUTPUT ;
    USE SIGNAL ;
    PORT
      LAYER M4 ;
        RECT 0.000000 257.280000 0.200000 257.480000 ;
    END
  END cp_ctrl[242]
  PIN cp_ctrl[241]
    DIRECTION OUTPUT ;
    USE SIGNAL ;
    PORT
      LAYER M4 ;
        RECT 0.000000 258.260000 0.200000 258.460000 ;
    END
  END cp_ctrl[241]
  PIN cp_ctrl[240]
    DIRECTION OUTPUT ;
    USE SIGNAL ;
    PORT
      LAYER M4 ;
        RECT 0.000000 259.240000 0.200000 259.440000 ;
    END
  END cp_ctrl[240]
  PIN cp_ctrl[239]
    DIRECTION OUTPUT ;
    USE SIGNAL ;
    PORT
      LAYER M4 ;
        RECT 0.000000 260.220000 0.200000 260.420000 ;
    END
  END cp_ctrl[239]
  PIN cp_ctrl[238]
    DIRECTION OUTPUT ;
    USE SIGNAL ;
    PORT
      LAYER M4 ;
        RECT 0.000000 262.180000 0.200000 262.380000 ;
    END
  END cp_ctrl[238]
  PIN cp_ctrl[237]
    DIRECTION OUTPUT ;
    USE SIGNAL ;
    PORT
      LAYER M4 ;
        RECT 0.000000 263.160000 0.200000 263.360000 ;
    END
  END cp_ctrl[237]
  PIN cp_ctrl[236]
    DIRECTION OUTPUT ;
    USE SIGNAL ;
    PORT
      LAYER M4 ;
        RECT 0.000000 264.140000 0.200000 264.340000 ;
    END
  END cp_ctrl[236]
  PIN cp_ctrl[235]
    DIRECTION OUTPUT ;
    USE SIGNAL ;
    PORT
      LAYER M4 ;
        RECT 0.000000 265.120000 0.200000 265.320000 ;
    END
  END cp_ctrl[235]
  PIN cp_ctrl[234]
    DIRECTION OUTPUT ;
    USE SIGNAL ;
    PORT
      LAYER M4 ;
        RECT 0.000000 266.100000 0.200000 266.300000 ;
    END
  END cp_ctrl[234]
  PIN cp_ctrl[233]
    DIRECTION OUTPUT ;
    USE SIGNAL ;
    PORT
      LAYER M4 ;
        RECT 0.000000 267.080000 0.200000 267.280000 ;
    END
  END cp_ctrl[233]
  PIN cp_ctrl[232]
    DIRECTION OUTPUT ;
    USE SIGNAL ;
    PORT
      LAYER M4 ;
        RECT 0.000000 268.060000 0.200000 268.260000 ;
    END
  END cp_ctrl[232]
  PIN cp_ctrl[231]
    DIRECTION OUTPUT ;
    USE SIGNAL ;
    PORT
      LAYER M4 ;
        RECT 0.000000 269.040000 0.200000 269.240000 ;
    END
  END cp_ctrl[231]
  PIN cp_ctrl[230]
    DIRECTION OUTPUT ;
    USE SIGNAL ;
    PORT
      LAYER M4 ;
        RECT 0.000000 270.020000 0.200000 270.220000 ;
    END
  END cp_ctrl[230]
  PIN cp_ctrl[229]
    DIRECTION OUTPUT ;
    USE SIGNAL ;
    PORT
      LAYER M4 ;
        RECT 0.000000 271.000000 0.200000 271.200000 ;
    END
  END cp_ctrl[229]
  PIN cp_ctrl[228]
    DIRECTION OUTPUT ;
    USE SIGNAL ;
    PORT
      LAYER M4 ;
        RECT 0.000000 271.980000 0.200000 272.180000 ;
    END
  END cp_ctrl[228]
  PIN cp_ctrl[227]
    DIRECTION OUTPUT ;
    USE SIGNAL ;
    PORT
      LAYER M4 ;
        RECT 0.000000 272.960000 0.200000 273.160000 ;
    END
  END cp_ctrl[227]
  PIN cp_ctrl[226]
    DIRECTION OUTPUT ;
    USE SIGNAL ;
    PORT
      LAYER M4 ;
        RECT 0.000000 273.940000 0.200000 274.140000 ;
    END
  END cp_ctrl[226]
  PIN cp_ctrl[225]
    DIRECTION OUTPUT ;
    USE SIGNAL ;
    PORT
      LAYER M4 ;
        RECT 0.000000 274.920000 0.200000 275.120000 ;
    END
  END cp_ctrl[225]
  PIN cp_ctrl[224]
    DIRECTION OUTPUT ;
    USE SIGNAL ;
    PORT
      LAYER M4 ;
        RECT 0.000000 276.880000 0.200000 277.080000 ;
    END
  END cp_ctrl[224]
  PIN cp_ctrl[223]
    DIRECTION OUTPUT ;
    USE SIGNAL ;
    PORT
      LAYER M4 ;
        RECT 0.000000 277.860000 0.200000 278.060000 ;
    END
  END cp_ctrl[223]
  PIN cp_ctrl[222]
    DIRECTION OUTPUT ;
    USE SIGNAL ;
    PORT
      LAYER M4 ;
        RECT 0.000000 278.840000 0.200000 279.040000 ;
    END
  END cp_ctrl[222]
  PIN cp_ctrl[221]
    DIRECTION OUTPUT ;
    USE SIGNAL ;
    PORT
      LAYER M4 ;
        RECT 0.000000 279.820000 0.200000 280.020000 ;
    END
  END cp_ctrl[221]
  PIN cp_ctrl[220]
    DIRECTION OUTPUT ;
    USE SIGNAL ;
    PORT
      LAYER M4 ;
        RECT 0.000000 280.800000 0.200000 281.000000 ;
    END
  END cp_ctrl[220]
  PIN cp_ctrl[219]
    DIRECTION OUTPUT ;
    USE SIGNAL ;
    PORT
      LAYER M4 ;
        RECT 0.000000 281.780000 0.200000 281.980000 ;
    END
  END cp_ctrl[219]
  PIN cp_ctrl[218]
    DIRECTION OUTPUT ;
    USE SIGNAL ;
    PORT
      LAYER M4 ;
        RECT 0.000000 282.760000 0.200000 282.960000 ;
    END
  END cp_ctrl[218]
  PIN cp_ctrl[217]
    DIRECTION OUTPUT ;
    USE SIGNAL ;
    PORT
      LAYER M4 ;
        RECT 0.000000 283.740000 0.200000 283.940000 ;
    END
  END cp_ctrl[217]
  PIN cp_ctrl[216]
    DIRECTION OUTPUT ;
    USE SIGNAL ;
    PORT
      LAYER M4 ;
        RECT 0.000000 284.720000 0.200000 284.920000 ;
    END
  END cp_ctrl[216]
  PIN cp_ctrl[215]
    DIRECTION OUTPUT ;
    USE SIGNAL ;
    PORT
      LAYER M4 ;
        RECT 0.000000 285.700000 0.200000 285.900000 ;
    END
  END cp_ctrl[215]
  PIN cp_ctrl[214]
    DIRECTION OUTPUT ;
    USE SIGNAL ;
    PORT
      LAYER M4 ;
        RECT 0.000000 286.680000 0.200000 286.880000 ;
    END
  END cp_ctrl[214]
  PIN cp_ctrl[213]
    DIRECTION OUTPUT ;
    USE SIGNAL ;
    PORT
      LAYER M4 ;
        RECT 0.000000 287.660000 0.200000 287.860000 ;
    END
  END cp_ctrl[213]
  PIN cp_ctrl[212]
    DIRECTION OUTPUT ;
    USE SIGNAL ;
    PORT
      LAYER M4 ;
        RECT 0.000000 288.640000 0.200000 288.840000 ;
    END
  END cp_ctrl[212]
  PIN cp_ctrl[211]
    DIRECTION OUTPUT ;
    USE SIGNAL ;
    PORT
      LAYER M4 ;
        RECT 0.000000 289.620000 0.200000 289.820000 ;
    END
  END cp_ctrl[211]
  PIN cp_ctrl[210]
    DIRECTION OUTPUT ;
    USE SIGNAL ;
    PORT
      LAYER M4 ;
        RECT 0.000000 290.600000 0.200000 290.800000 ;
    END
  END cp_ctrl[210]
  PIN cp_ctrl[209]
    DIRECTION OUTPUT ;
    USE SIGNAL ;
    PORT
      LAYER M4 ;
        RECT 0.000000 212.750000 0.200000 212.950000 ;
    END
  END cp_ctrl[209]
  PIN cp_ctrl[208]
    DIRECTION OUTPUT ;
    USE SIGNAL ;
    PORT
      LAYER M4 ;
        RECT 0.000000 227.450000 0.200000 227.650000 ;
    END
  END cp_ctrl[208]
  PIN cp_ctrl[207]
    DIRECTION OUTPUT ;
    USE SIGNAL ;
    PORT
      LAYER M4 ;
        RECT 0.000000 200.010000 0.200000 200.210000 ;
    END
  END cp_ctrl[207]
  PIN cp_ctrl[206]
    DIRECTION OUTPUT ;
    USE SIGNAL ;
    PORT
      LAYER M4 ;
        RECT 0.000000 200.990000 0.200000 201.190000 ;
    END
  END cp_ctrl[206]
  PIN cp_ctrl[205]
    DIRECTION OUTPUT ;
    USE SIGNAL ;
    PORT
      LAYER M4 ;
        RECT 0.000000 201.970000 0.200000 202.170000 ;
    END
  END cp_ctrl[205]
  PIN cp_ctrl[204]
    DIRECTION OUTPUT ;
    USE SIGNAL ;
    PORT
      LAYER M4 ;
        RECT 0.000000 202.950000 0.200000 203.150000 ;
    END
  END cp_ctrl[204]
  PIN cp_ctrl[203]
    DIRECTION OUTPUT ;
    USE SIGNAL ;
    PORT
      LAYER M4 ;
        RECT 0.000000 203.930000 0.200000 204.130000 ;
    END
  END cp_ctrl[203]
  PIN cp_ctrl[202]
    DIRECTION OUTPUT ;
    USE SIGNAL ;
    PORT
      LAYER M4 ;
        RECT 0.000000 204.910000 0.200000 205.110000 ;
    END
  END cp_ctrl[202]
  PIN cp_ctrl[201]
    DIRECTION OUTPUT ;
    USE SIGNAL ;
    PORT
      LAYER M4 ;
        RECT 0.000000 205.890000 0.200000 206.090000 ;
    END
  END cp_ctrl[201]
  PIN cp_ctrl[200]
    DIRECTION OUTPUT ;
    USE SIGNAL ;
    PORT
      LAYER M4 ;
        RECT 0.000000 208.830000 0.200000 209.030000 ;
    END
  END cp_ctrl[200]
  PIN cp_ctrl[199]
    DIRECTION OUTPUT ;
    USE SIGNAL ;
    PORT
      LAYER M4 ;
        RECT 0.000000 209.810000 0.200000 210.010000 ;
    END
  END cp_ctrl[199]
  PIN cp_ctrl[198]
    DIRECTION OUTPUT ;
    USE SIGNAL ;
    PORT
      LAYER M4 ;
        RECT 0.000000 210.790000 0.200000 210.990000 ;
    END
  END cp_ctrl[198]
  PIN cp_ctrl[197]
    DIRECTION OUTPUT ;
    USE SIGNAL ;
    PORT
      LAYER M4 ;
        RECT 0.000000 211.770000 0.200000 211.970000 ;
    END
  END cp_ctrl[197]
  PIN cp_ctrl[196]
    DIRECTION OUTPUT ;
    USE SIGNAL ;
    PORT
      LAYER M4 ;
        RECT 0.000000 213.730000 0.200000 213.930000 ;
    END
  END cp_ctrl[196]
  PIN cp_ctrl[195]
    DIRECTION OUTPUT ;
    USE SIGNAL ;
    PORT
      LAYER M4 ;
        RECT 0.000000 214.710000 0.200000 214.910000 ;
    END
  END cp_ctrl[195]
  PIN cp_ctrl[194]
    DIRECTION OUTPUT ;
    USE SIGNAL ;
    PORT
      LAYER M4 ;
        RECT 0.000000 215.690000 0.200000 215.890000 ;
    END
  END cp_ctrl[194]
  PIN cp_ctrl[193]
    DIRECTION OUTPUT ;
    USE SIGNAL ;
    PORT
      LAYER M4 ;
        RECT 0.000000 216.670000 0.200000 216.870000 ;
    END
  END cp_ctrl[193]
  PIN cp_ctrl[192]
    DIRECTION OUTPUT ;
    USE SIGNAL ;
    PORT
      LAYER M4 ;
        RECT 0.000000 217.650000 0.200000 217.850000 ;
    END
  END cp_ctrl[192]
  PIN cp_ctrl[191]
    DIRECTION OUTPUT ;
    USE SIGNAL ;
    PORT
      LAYER M4 ;
        RECT 0.000000 218.630000 0.200000 218.830000 ;
    END
  END cp_ctrl[191]
  PIN cp_ctrl[190]
    DIRECTION OUTPUT ;
    USE SIGNAL ;
    PORT
      LAYER M4 ;
        RECT 0.000000 219.610000 0.200000 219.810000 ;
    END
  END cp_ctrl[190]
  PIN cp_ctrl[189]
    DIRECTION OUTPUT ;
    USE SIGNAL ;
    PORT
      LAYER M4 ;
        RECT 0.000000 220.590000 0.200000 220.790000 ;
    END
  END cp_ctrl[189]
  PIN cp_ctrl[188]
    DIRECTION OUTPUT ;
    USE SIGNAL ;
    PORT
      LAYER M4 ;
        RECT 0.000000 221.570000 0.200000 221.770000 ;
    END
  END cp_ctrl[188]
  PIN cp_ctrl[187]
    DIRECTION OUTPUT ;
    USE SIGNAL ;
    PORT
      LAYER M4 ;
        RECT 0.000000 222.550000 0.200000 222.750000 ;
    END
  END cp_ctrl[187]
  PIN cp_ctrl[186]
    DIRECTION OUTPUT ;
    USE SIGNAL ;
    PORT
      LAYER M4 ;
        RECT 0.000000 223.530000 0.200000 223.730000 ;
    END
  END cp_ctrl[186]
  PIN cp_ctrl[185]
    DIRECTION OUTPUT ;
    USE SIGNAL ;
    PORT
      LAYER M4 ;
        RECT 0.000000 224.510000 0.200000 224.710000 ;
    END
  END cp_ctrl[185]
  PIN cp_ctrl[184]
    DIRECTION OUTPUT ;
    USE SIGNAL ;
    PORT
      LAYER M4 ;
        RECT 0.000000 225.490000 0.200000 225.690000 ;
    END
  END cp_ctrl[184]
  PIN cp_ctrl[183]
    DIRECTION OUTPUT ;
    USE SIGNAL ;
    PORT
      LAYER M4 ;
        RECT 0.000000 226.470000 0.200000 226.670000 ;
    END
  END cp_ctrl[183]
  PIN cp_ctrl[182]
    DIRECTION OUTPUT ;
    USE SIGNAL ;
    PORT
      LAYER M4 ;
        RECT 0.000000 228.430000 0.200000 228.630000 ;
    END
  END cp_ctrl[182]
  PIN cp_ctrl[181]
    DIRECTION OUTPUT ;
    USE SIGNAL ;
    PORT
      LAYER M4 ;
        RECT 0.000000 229.410000 0.200000 229.610000 ;
    END
  END cp_ctrl[181]
  PIN cp_ctrl[180]
    DIRECTION OUTPUT ;
    USE SIGNAL ;
    PORT
      LAYER M4 ;
        RECT 0.000000 230.390000 0.200000 230.590000 ;
    END
  END cp_ctrl[180]
  PIN cp_ctrl[179]
    DIRECTION OUTPUT ;
    USE SIGNAL ;
    PORT
      LAYER M4 ;
        RECT 0.000000 231.370000 0.200000 231.570000 ;
    END
  END cp_ctrl[179]
  PIN cp_ctrl[178]
    DIRECTION OUTPUT ;
    USE SIGNAL ;
    PORT
      LAYER M4 ;
        RECT 0.000000 232.350000 0.200000 232.550000 ;
    END
  END cp_ctrl[178]
  PIN cp_ctrl[177]
    DIRECTION OUTPUT ;
    USE SIGNAL ;
    PORT
      LAYER M4 ;
        RECT 0.000000 233.330000 0.200000 233.530000 ;
    END
  END cp_ctrl[177]
  PIN cp_ctrl[176]
    DIRECTION OUTPUT ;
    USE SIGNAL ;
    PORT
      LAYER M4 ;
        RECT 0.000000 234.310000 0.200000 234.510000 ;
    END
  END cp_ctrl[176]
  PIN cp_ctrl[175]
    DIRECTION OUTPUT ;
    USE SIGNAL ;
    PORT
      LAYER M4 ;
        RECT 0.000000 235.290000 0.200000 235.490000 ;
    END
  END cp_ctrl[175]
  PIN cp_ctrl[174]
    DIRECTION OUTPUT ;
    USE SIGNAL ;
    PORT
      LAYER M4 ;
        RECT 0.000000 236.270000 0.200000 236.470000 ;
    END
  END cp_ctrl[174]
  PIN cp_ctrl[173]
    DIRECTION OUTPUT ;
    USE SIGNAL ;
    PORT
      LAYER M4 ;
        RECT 0.000000 237.250000 0.200000 237.450000 ;
    END
  END cp_ctrl[173]
  PIN cp_ctrl[172]
    DIRECTION OUTPUT ;
    USE SIGNAL ;
    PORT
      LAYER M4 ;
        RECT 0.000000 238.230000 0.200000 238.430000 ;
    END
  END cp_ctrl[172]
  PIN cp_ctrl[171]
    DIRECTION OUTPUT ;
    USE SIGNAL ;
    PORT
      LAYER M4 ;
        RECT 0.000000 239.210000 0.200000 239.410000 ;
    END
  END cp_ctrl[171]
  PIN cp_ctrl[170]
    DIRECTION OUTPUT ;
    USE SIGNAL ;
    PORT
      LAYER M4 ;
        RECT 0.000000 240.190000 0.200000 240.390000 ;
    END
  END cp_ctrl[170]
  PIN cp_ctrl[169]
    DIRECTION OUTPUT ;
    USE SIGNAL ;
    PORT
      LAYER M4 ;
        RECT 0.000000 241.170000 0.200000 241.370000 ;
    END
  END cp_ctrl[169]
  PIN cp_ctrl[168]
    DIRECTION OUTPUT ;
    USE SIGNAL ;
    PORT
      LAYER M4 ;
        RECT 0.000000 242.150000 0.200000 242.350000 ;
    END
  END cp_ctrl[168]
  PIN cp_ctrl[167]
    DIRECTION OUTPUT ;
    USE SIGNAL ;
    PORT
      LAYER M4 ;
        RECT 0.000000 164.300000 0.200000 164.500000 ;
    END
  END cp_ctrl[167]
  PIN cp_ctrl[166]
    DIRECTION OUTPUT ;
    USE SIGNAL ;
    PORT
      LAYER M4 ;
        RECT 0.000000 179.000000 0.200000 179.200000 ;
    END
  END cp_ctrl[166]
  PIN cp_ctrl[165]
    DIRECTION OUTPUT ;
    USE SIGNAL ;
    PORT
      LAYER M4 ;
        RECT 0.000000 151.560000 0.200000 151.760000 ;
    END
  END cp_ctrl[165]
  PIN cp_ctrl[164]
    DIRECTION OUTPUT ;
    USE SIGNAL ;
    PORT
      LAYER M4 ;
        RECT 0.000000 152.540000 0.200000 152.740000 ;
    END
  END cp_ctrl[164]
  PIN cp_ctrl[163]
    DIRECTION OUTPUT ;
    USE SIGNAL ;
    PORT
      LAYER M4 ;
        RECT 0.000000 153.520000 0.200000 153.720000 ;
    END
  END cp_ctrl[163]
  PIN cp_ctrl[162]
    DIRECTION OUTPUT ;
    USE SIGNAL ;
    PORT
      LAYER M4 ;
        RECT 0.000000 154.500000 0.200000 154.700000 ;
    END
  END cp_ctrl[162]
  PIN cp_ctrl[161]
    DIRECTION OUTPUT ;
    USE SIGNAL ;
    PORT
      LAYER M4 ;
        RECT 0.000000 155.480000 0.200000 155.680000 ;
    END
  END cp_ctrl[161]
  PIN cp_ctrl[160]
    DIRECTION OUTPUT ;
    USE SIGNAL ;
    PORT
      LAYER M4 ;
        RECT 0.000000 156.460000 0.200000 156.660000 ;
    END
  END cp_ctrl[160]
  PIN cp_ctrl[159]
    DIRECTION OUTPUT ;
    USE SIGNAL ;
    PORT
      LAYER M4 ;
        RECT 0.000000 157.440000 0.200000 157.640000 ;
    END
  END cp_ctrl[159]
  PIN cp_ctrl[158]
    DIRECTION OUTPUT ;
    USE SIGNAL ;
    PORT
      LAYER M4 ;
        RECT 0.000000 160.380000 0.200000 160.580000 ;
    END
  END cp_ctrl[158]
  PIN cp_ctrl[157]
    DIRECTION OUTPUT ;
    USE SIGNAL ;
    PORT
      LAYER M4 ;
        RECT 0.000000 161.360000 0.200000 161.560000 ;
    END
  END cp_ctrl[157]
  PIN cp_ctrl[156]
    DIRECTION OUTPUT ;
    USE SIGNAL ;
    PORT
      LAYER M4 ;
        RECT 0.000000 162.340000 0.200000 162.540000 ;
    END
  END cp_ctrl[156]
  PIN cp_ctrl[155]
    DIRECTION OUTPUT ;
    USE SIGNAL ;
    PORT
      LAYER M4 ;
        RECT 0.000000 163.320000 0.200000 163.520000 ;
    END
  END cp_ctrl[155]
  PIN cp_ctrl[154]
    DIRECTION OUTPUT ;
    USE SIGNAL ;
    PORT
      LAYER M4 ;
        RECT 0.000000 165.280000 0.200000 165.480000 ;
    END
  END cp_ctrl[154]
  PIN cp_ctrl[153]
    DIRECTION OUTPUT ;
    USE SIGNAL ;
    PORT
      LAYER M4 ;
        RECT 0.000000 166.260000 0.200000 166.460000 ;
    END
  END cp_ctrl[153]
  PIN cp_ctrl[152]
    DIRECTION OUTPUT ;
    USE SIGNAL ;
    PORT
      LAYER M4 ;
        RECT 0.000000 167.240000 0.200000 167.440000 ;
    END
  END cp_ctrl[152]
  PIN cp_ctrl[151]
    DIRECTION OUTPUT ;
    USE SIGNAL ;
    PORT
      LAYER M4 ;
        RECT 0.000000 168.220000 0.200000 168.420000 ;
    END
  END cp_ctrl[151]
  PIN cp_ctrl[150]
    DIRECTION OUTPUT ;
    USE SIGNAL ;
    PORT
      LAYER M4 ;
        RECT 0.000000 169.200000 0.200000 169.400000 ;
    END
  END cp_ctrl[150]
  PIN cp_ctrl[149]
    DIRECTION OUTPUT ;
    USE SIGNAL ;
    PORT
      LAYER M4 ;
        RECT 0.000000 170.180000 0.200000 170.380000 ;
    END
  END cp_ctrl[149]
  PIN cp_ctrl[148]
    DIRECTION OUTPUT ;
    USE SIGNAL ;
    PORT
      LAYER M4 ;
        RECT 0.000000 171.160000 0.200000 171.360000 ;
    END
  END cp_ctrl[148]
  PIN cp_ctrl[147]
    DIRECTION OUTPUT ;
    USE SIGNAL ;
    PORT
      LAYER M4 ;
        RECT 0.000000 172.140000 0.200000 172.340000 ;
    END
  END cp_ctrl[147]
  PIN cp_ctrl[146]
    DIRECTION OUTPUT ;
    USE SIGNAL ;
    PORT
      LAYER M4 ;
        RECT 0.000000 173.120000 0.200000 173.320000 ;
    END
  END cp_ctrl[146]
  PIN cp_ctrl[145]
    DIRECTION OUTPUT ;
    USE SIGNAL ;
    PORT
      LAYER M4 ;
        RECT 0.000000 174.100000 0.200000 174.300000 ;
    END
  END cp_ctrl[145]
  PIN cp_ctrl[144]
    DIRECTION OUTPUT ;
    USE SIGNAL ;
    PORT
      LAYER M4 ;
        RECT 0.000000 175.080000 0.200000 175.280000 ;
    END
  END cp_ctrl[144]
  PIN cp_ctrl[143]
    DIRECTION OUTPUT ;
    USE SIGNAL ;
    PORT
      LAYER M4 ;
        RECT 0.000000 176.060000 0.200000 176.260000 ;
    END
  END cp_ctrl[143]
  PIN cp_ctrl[142]
    DIRECTION OUTPUT ;
    USE SIGNAL ;
    PORT
      LAYER M4 ;
        RECT 0.000000 177.040000 0.200000 177.240000 ;
    END
  END cp_ctrl[142]
  PIN cp_ctrl[141]
    DIRECTION OUTPUT ;
    USE SIGNAL ;
    PORT
      LAYER M4 ;
        RECT 0.000000 178.020000 0.200000 178.220000 ;
    END
  END cp_ctrl[141]
  PIN cp_ctrl[140]
    DIRECTION OUTPUT ;
    USE SIGNAL ;
    PORT
      LAYER M4 ;
        RECT 0.000000 179.980000 0.200000 180.180000 ;
    END
  END cp_ctrl[140]
  PIN cp_ctrl[139]
    DIRECTION OUTPUT ;
    USE SIGNAL ;
    PORT
      LAYER M4 ;
        RECT 0.000000 180.960000 0.200000 181.160000 ;
    END
  END cp_ctrl[139]
  PIN cp_ctrl[138]
    DIRECTION OUTPUT ;
    USE SIGNAL ;
    PORT
      LAYER M4 ;
        RECT 0.000000 181.940000 0.200000 182.140000 ;
    END
  END cp_ctrl[138]
  PIN cp_ctrl[137]
    DIRECTION OUTPUT ;
    USE SIGNAL ;
    PORT
      LAYER M4 ;
        RECT 0.000000 182.920000 0.200000 183.120000 ;
    END
  END cp_ctrl[137]
  PIN cp_ctrl[136]
    DIRECTION OUTPUT ;
    USE SIGNAL ;
    PORT
      LAYER M4 ;
        RECT 0.000000 183.900000 0.200000 184.100000 ;
    END
  END cp_ctrl[136]
  PIN cp_ctrl[135]
    DIRECTION OUTPUT ;
    USE SIGNAL ;
    PORT
      LAYER M4 ;
        RECT 0.000000 184.880000 0.200000 185.080000 ;
    END
  END cp_ctrl[135]
  PIN cp_ctrl[134]
    DIRECTION OUTPUT ;
    USE SIGNAL ;
    PORT
      LAYER M4 ;
        RECT 0.000000 185.860000 0.200000 186.060000 ;
    END
  END cp_ctrl[134]
  PIN cp_ctrl[133]
    DIRECTION OUTPUT ;
    USE SIGNAL ;
    PORT
      LAYER M4 ;
        RECT 0.000000 186.840000 0.200000 187.040000 ;
    END
  END cp_ctrl[133]
  PIN cp_ctrl[132]
    DIRECTION OUTPUT ;
    USE SIGNAL ;
    PORT
      LAYER M4 ;
        RECT 0.000000 187.820000 0.200000 188.020000 ;
    END
  END cp_ctrl[132]
  PIN cp_ctrl[131]
    DIRECTION OUTPUT ;
    USE SIGNAL ;
    PORT
      LAYER M4 ;
        RECT 0.000000 188.800000 0.200000 189.000000 ;
    END
  END cp_ctrl[131]
  PIN cp_ctrl[130]
    DIRECTION OUTPUT ;
    USE SIGNAL ;
    PORT
      LAYER M4 ;
        RECT 0.000000 189.780000 0.200000 189.980000 ;
    END
  END cp_ctrl[130]
  PIN cp_ctrl[129]
    DIRECTION OUTPUT ;
    USE SIGNAL ;
    PORT
      LAYER M4 ;
        RECT 0.000000 190.760000 0.200000 190.960000 ;
    END
  END cp_ctrl[129]
  PIN cp_ctrl[128]
    DIRECTION OUTPUT ;
    USE SIGNAL ;
    PORT
      LAYER M4 ;
        RECT 0.000000 191.740000 0.200000 191.940000 ;
    END
  END cp_ctrl[128]
  PIN cp_ctrl[127]
    DIRECTION OUTPUT ;
    USE SIGNAL ;
    PORT
      LAYER M4 ;
        RECT 0.000000 192.720000 0.200000 192.920000 ;
    END
  END cp_ctrl[127]
  PIN cp_ctrl[126]
    DIRECTION OUTPUT ;
    USE SIGNAL ;
    PORT
      LAYER M4 ;
        RECT 0.000000 193.700000 0.200000 193.900000 ;
    END
  END cp_ctrl[126]
  PIN cp_ctrl[125]
    DIRECTION OUTPUT ;
    USE SIGNAL ;
    PORT
      LAYER M4 ;
        RECT 0.000000 115.850000 0.200000 116.050000 ;
    END
  END cp_ctrl[125]
  PIN cp_ctrl[124]
    DIRECTION OUTPUT ;
    USE SIGNAL ;
    PORT
      LAYER M4 ;
        RECT 0.000000 130.550000 0.200000 130.750000 ;
    END
  END cp_ctrl[124]
  PIN cp_ctrl[123]
    DIRECTION OUTPUT ;
    USE SIGNAL ;
    PORT
      LAYER M4 ;
        RECT 0.000000 103.110000 0.200000 103.310000 ;
    END
  END cp_ctrl[123]
  PIN cp_ctrl[122]
    DIRECTION OUTPUT ;
    USE SIGNAL ;
    PORT
      LAYER M4 ;
        RECT 0.000000 104.090000 0.200000 104.290000 ;
    END
  END cp_ctrl[122]
  PIN cp_ctrl[121]
    DIRECTION OUTPUT ;
    USE SIGNAL ;
    PORT
      LAYER M4 ;
        RECT 0.000000 105.070000 0.200000 105.270000 ;
    END
  END cp_ctrl[121]
  PIN cp_ctrl[120]
    DIRECTION OUTPUT ;
    USE SIGNAL ;
    PORT
      LAYER M4 ;
        RECT 0.000000 106.050000 0.200000 106.250000 ;
    END
  END cp_ctrl[120]
  PIN cp_ctrl[119]
    DIRECTION OUTPUT ;
    USE SIGNAL ;
    PORT
      LAYER M4 ;
        RECT 0.000000 107.030000 0.200000 107.230000 ;
    END
  END cp_ctrl[119]
  PIN cp_ctrl[118]
    DIRECTION OUTPUT ;
    USE SIGNAL ;
    PORT
      LAYER M4 ;
        RECT 0.000000 108.010000 0.200000 108.210000 ;
    END
  END cp_ctrl[118]
  PIN cp_ctrl[117]
    DIRECTION OUTPUT ;
    USE SIGNAL ;
    PORT
      LAYER M4 ;
        RECT 0.000000 108.990000 0.200000 109.190000 ;
    END
  END cp_ctrl[117]
  PIN cp_ctrl[116]
    DIRECTION OUTPUT ;
    USE SIGNAL ;
    PORT
      LAYER M4 ;
        RECT 0.000000 111.930000 0.200000 112.130000 ;
    END
  END cp_ctrl[116]
  PIN cp_ctrl[115]
    DIRECTION OUTPUT ;
    USE SIGNAL ;
    PORT
      LAYER M4 ;
        RECT 0.000000 112.910000 0.200000 113.110000 ;
    END
  END cp_ctrl[115]
  PIN cp_ctrl[114]
    DIRECTION OUTPUT ;
    USE SIGNAL ;
    PORT
      LAYER M4 ;
        RECT 0.000000 113.890000 0.200000 114.090000 ;
    END
  END cp_ctrl[114]
  PIN cp_ctrl[113]
    DIRECTION OUTPUT ;
    USE SIGNAL ;
    PORT
      LAYER M4 ;
        RECT 0.000000 114.870000 0.200000 115.070000 ;
    END
  END cp_ctrl[113]
  PIN cp_ctrl[112]
    DIRECTION OUTPUT ;
    USE SIGNAL ;
    PORT
      LAYER M4 ;
        RECT 0.000000 116.830000 0.200000 117.030000 ;
    END
  END cp_ctrl[112]
  PIN cp_ctrl[111]
    DIRECTION OUTPUT ;
    USE SIGNAL ;
    PORT
      LAYER M4 ;
        RECT 0.000000 117.810000 0.200000 118.010000 ;
    END
  END cp_ctrl[111]
  PIN cp_ctrl[110]
    DIRECTION OUTPUT ;
    USE SIGNAL ;
    PORT
      LAYER M4 ;
        RECT 0.000000 118.790000 0.200000 118.990000 ;
    END
  END cp_ctrl[110]
  PIN cp_ctrl[109]
    DIRECTION OUTPUT ;
    USE SIGNAL ;
    PORT
      LAYER M4 ;
        RECT 0.000000 119.770000 0.200000 119.970000 ;
    END
  END cp_ctrl[109]
  PIN cp_ctrl[108]
    DIRECTION OUTPUT ;
    USE SIGNAL ;
    PORT
      LAYER M4 ;
        RECT 0.000000 120.750000 0.200000 120.950000 ;
    END
  END cp_ctrl[108]
  PIN cp_ctrl[107]
    DIRECTION OUTPUT ;
    USE SIGNAL ;
    PORT
      LAYER M4 ;
        RECT 0.000000 121.730000 0.200000 121.930000 ;
    END
  END cp_ctrl[107]
  PIN cp_ctrl[106]
    DIRECTION OUTPUT ;
    USE SIGNAL ;
    PORT
      LAYER M4 ;
        RECT 0.000000 122.710000 0.200000 122.910000 ;
    END
  END cp_ctrl[106]
  PIN cp_ctrl[105]
    DIRECTION OUTPUT ;
    USE SIGNAL ;
    PORT
      LAYER M4 ;
        RECT 0.000000 123.690000 0.200000 123.890000 ;
    END
  END cp_ctrl[105]
  PIN cp_ctrl[104]
    DIRECTION OUTPUT ;
    USE SIGNAL ;
    PORT
      LAYER M4 ;
        RECT 0.000000 124.670000 0.200000 124.870000 ;
    END
  END cp_ctrl[104]
  PIN cp_ctrl[103]
    DIRECTION OUTPUT ;
    USE SIGNAL ;
    PORT
      LAYER M4 ;
        RECT 0.000000 125.650000 0.200000 125.850000 ;
    END
  END cp_ctrl[103]
  PIN cp_ctrl[102]
    DIRECTION OUTPUT ;
    USE SIGNAL ;
    PORT
      LAYER M4 ;
        RECT 0.000000 126.630000 0.200000 126.830000 ;
    END
  END cp_ctrl[102]
  PIN cp_ctrl[101]
    DIRECTION OUTPUT ;
    USE SIGNAL ;
    PORT
      LAYER M4 ;
        RECT 0.000000 127.610000 0.200000 127.810000 ;
    END
  END cp_ctrl[101]
  PIN cp_ctrl[100]
    DIRECTION OUTPUT ;
    USE SIGNAL ;
    PORT
      LAYER M4 ;
        RECT 0.000000 128.590000 0.200000 128.790000 ;
    END
  END cp_ctrl[100]
  PIN cp_ctrl[99]
    DIRECTION OUTPUT ;
    USE SIGNAL ;
    PORT
      LAYER M4 ;
        RECT 0.000000 129.570000 0.200000 129.770000 ;
    END
  END cp_ctrl[99]
  PIN cp_ctrl[98]
    DIRECTION OUTPUT ;
    USE SIGNAL ;
    PORT
      LAYER M4 ;
        RECT 0.000000 131.530000 0.200000 131.730000 ;
    END
  END cp_ctrl[98]
  PIN cp_ctrl[97]
    DIRECTION OUTPUT ;
    USE SIGNAL ;
    PORT
      LAYER M4 ;
        RECT 0.000000 132.510000 0.200000 132.710000 ;
    END
  END cp_ctrl[97]
  PIN cp_ctrl[96]
    DIRECTION OUTPUT ;
    USE SIGNAL ;
    PORT
      LAYER M4 ;
        RECT 0.000000 133.490000 0.200000 133.690000 ;
    END
  END cp_ctrl[96]
  PIN cp_ctrl[95]
    DIRECTION OUTPUT ;
    USE SIGNAL ;
    PORT
      LAYER M4 ;
        RECT 0.000000 134.470000 0.200000 134.670000 ;
    END
  END cp_ctrl[95]
  PIN cp_ctrl[94]
    DIRECTION OUTPUT ;
    USE SIGNAL ;
    PORT
      LAYER M4 ;
        RECT 0.000000 135.450000 0.200000 135.650000 ;
    END
  END cp_ctrl[94]
  PIN cp_ctrl[93]
    DIRECTION OUTPUT ;
    USE SIGNAL ;
    PORT
      LAYER M4 ;
        RECT 0.000000 136.430000 0.200000 136.630000 ;
    END
  END cp_ctrl[93]
  PIN cp_ctrl[92]
    DIRECTION OUTPUT ;
    USE SIGNAL ;
    PORT
      LAYER M4 ;
        RECT 0.000000 137.410000 0.200000 137.610000 ;
    END
  END cp_ctrl[92]
  PIN cp_ctrl[91]
    DIRECTION OUTPUT ;
    USE SIGNAL ;
    PORT
      LAYER M4 ;
        RECT 0.000000 138.390000 0.200000 138.590000 ;
    END
  END cp_ctrl[91]
  PIN cp_ctrl[90]
    DIRECTION OUTPUT ;
    USE SIGNAL ;
    PORT
      LAYER M4 ;
        RECT 0.000000 139.370000 0.200000 139.570000 ;
    END
  END cp_ctrl[90]
  PIN cp_ctrl[89]
    DIRECTION OUTPUT ;
    USE SIGNAL ;
    PORT
      LAYER M4 ;
        RECT 0.000000 140.350000 0.200000 140.550000 ;
    END
  END cp_ctrl[89]
  PIN cp_ctrl[88]
    DIRECTION OUTPUT ;
    USE SIGNAL ;
    PORT
      LAYER M4 ;
        RECT 0.000000 141.330000 0.200000 141.530000 ;
    END
  END cp_ctrl[88]
  PIN cp_ctrl[87]
    DIRECTION OUTPUT ;
    USE SIGNAL ;
    PORT
      LAYER M4 ;
        RECT 0.000000 142.310000 0.200000 142.510000 ;
    END
  END cp_ctrl[87]
  PIN cp_ctrl[86]
    DIRECTION OUTPUT ;
    USE SIGNAL ;
    PORT
      LAYER M4 ;
        RECT 0.000000 143.290000 0.200000 143.490000 ;
    END
  END cp_ctrl[86]
  PIN cp_ctrl[85]
    DIRECTION OUTPUT ;
    USE SIGNAL ;
    PORT
      LAYER M4 ;
        RECT 0.000000 144.270000 0.200000 144.470000 ;
    END
  END cp_ctrl[85]
  PIN cp_ctrl[84]
    DIRECTION OUTPUT ;
    USE SIGNAL ;
    PORT
      LAYER M4 ;
        RECT 0.000000 145.250000 0.200000 145.450000 ;
    END
  END cp_ctrl[84]
  PIN cp_ctrl[83]
    DIRECTION OUTPUT ;
    USE SIGNAL ;
    PORT
      LAYER M4 ;
        RECT 0.000000 67.400000 0.200000 67.600000 ;
    END
  END cp_ctrl[83]
  PIN cp_ctrl[82]
    DIRECTION OUTPUT ;
    USE SIGNAL ;
    PORT
      LAYER M4 ;
        RECT 0.000000 82.100000 0.200000 82.300000 ;
    END
  END cp_ctrl[82]
  PIN cp_ctrl[81]
    DIRECTION OUTPUT ;
    USE SIGNAL ;
    PORT
      LAYER M4 ;
        RECT 0.000000 54.660000 0.200000 54.860000 ;
    END
  END cp_ctrl[81]
  PIN cp_ctrl[80]
    DIRECTION OUTPUT ;
    USE SIGNAL ;
    PORT
      LAYER M4 ;
        RECT 0.000000 55.640000 0.200000 55.840000 ;
    END
  END cp_ctrl[80]
  PIN cp_ctrl[79]
    DIRECTION OUTPUT ;
    USE SIGNAL ;
    PORT
      LAYER M4 ;
        RECT 0.000000 56.620000 0.200000 56.820000 ;
    END
  END cp_ctrl[79]
  PIN cp_ctrl[78]
    DIRECTION OUTPUT ;
    USE SIGNAL ;
    PORT
      LAYER M4 ;
        RECT 0.000000 57.600000 0.200000 57.800000 ;
    END
  END cp_ctrl[78]
  PIN cp_ctrl[77]
    DIRECTION OUTPUT ;
    USE SIGNAL ;
    PORT
      LAYER M4 ;
        RECT 0.000000 58.580000 0.200000 58.780000 ;
    END
  END cp_ctrl[77]
  PIN cp_ctrl[76]
    DIRECTION OUTPUT ;
    USE SIGNAL ;
    PORT
      LAYER M4 ;
        RECT 0.000000 59.560000 0.200000 59.760000 ;
    END
  END cp_ctrl[76]
  PIN cp_ctrl[75]
    DIRECTION OUTPUT ;
    USE SIGNAL ;
    PORT
      LAYER M4 ;
        RECT 0.000000 60.540000 0.200000 60.740000 ;
    END
  END cp_ctrl[75]
  PIN cp_ctrl[74]
    DIRECTION OUTPUT ;
    USE SIGNAL ;
    PORT
      LAYER M4 ;
        RECT 0.000000 63.480000 0.200000 63.680000 ;
    END
  END cp_ctrl[74]
  PIN cp_ctrl[73]
    DIRECTION OUTPUT ;
    USE SIGNAL ;
    PORT
      LAYER M4 ;
        RECT 0.000000 64.460000 0.200000 64.660000 ;
    END
  END cp_ctrl[73]
  PIN cp_ctrl[72]
    DIRECTION OUTPUT ;
    USE SIGNAL ;
    PORT
      LAYER M4 ;
        RECT 0.000000 65.440000 0.200000 65.640000 ;
    END
  END cp_ctrl[72]
  PIN cp_ctrl[71]
    DIRECTION OUTPUT ;
    USE SIGNAL ;
    PORT
      LAYER M4 ;
        RECT 0.000000 66.420000 0.200000 66.620000 ;
    END
  END cp_ctrl[71]
  PIN cp_ctrl[70]
    DIRECTION OUTPUT ;
    USE SIGNAL ;
    PORT
      LAYER M4 ;
        RECT 0.000000 68.380000 0.200000 68.580000 ;
    END
  END cp_ctrl[70]
  PIN cp_ctrl[69]
    DIRECTION OUTPUT ;
    USE SIGNAL ;
    PORT
      LAYER M4 ;
        RECT 0.000000 69.360000 0.200000 69.560000 ;
    END
  END cp_ctrl[69]
  PIN cp_ctrl[68]
    DIRECTION OUTPUT ;
    USE SIGNAL ;
    PORT
      LAYER M4 ;
        RECT 0.000000 70.340000 0.200000 70.540000 ;
    END
  END cp_ctrl[68]
  PIN cp_ctrl[67]
    DIRECTION OUTPUT ;
    USE SIGNAL ;
    PORT
      LAYER M4 ;
        RECT 0.000000 71.320000 0.200000 71.520000 ;
    END
  END cp_ctrl[67]
  PIN cp_ctrl[66]
    DIRECTION OUTPUT ;
    USE SIGNAL ;
    PORT
      LAYER M4 ;
        RECT 0.000000 72.300000 0.200000 72.500000 ;
    END
  END cp_ctrl[66]
  PIN cp_ctrl[65]
    DIRECTION OUTPUT ;
    USE SIGNAL ;
    PORT
      LAYER M4 ;
        RECT 0.000000 73.280000 0.200000 73.480000 ;
    END
  END cp_ctrl[65]
  PIN cp_ctrl[64]
    DIRECTION OUTPUT ;
    USE SIGNAL ;
    PORT
      LAYER M4 ;
        RECT 0.000000 74.260000 0.200000 74.460000 ;
    END
  END cp_ctrl[64]
  PIN cp_ctrl[63]
    DIRECTION OUTPUT ;
    USE SIGNAL ;
    PORT
      LAYER M4 ;
        RECT 0.000000 75.240000 0.200000 75.440000 ;
    END
  END cp_ctrl[63]
  PIN cp_ctrl[62]
    DIRECTION OUTPUT ;
    USE SIGNAL ;
    PORT
      LAYER M4 ;
        RECT 0.000000 76.220000 0.200000 76.420000 ;
    END
  END cp_ctrl[62]
  PIN cp_ctrl[61]
    DIRECTION OUTPUT ;
    USE SIGNAL ;
    PORT
      LAYER M4 ;
        RECT 0.000000 77.200000 0.200000 77.400000 ;
    END
  END cp_ctrl[61]
  PIN cp_ctrl[60]
    DIRECTION OUTPUT ;
    USE SIGNAL ;
    PORT
      LAYER M4 ;
        RECT 0.000000 78.180000 0.200000 78.380000 ;
    END
  END cp_ctrl[60]
  PIN cp_ctrl[59]
    DIRECTION OUTPUT ;
    USE SIGNAL ;
    PORT
      LAYER M4 ;
        RECT 0.000000 79.160000 0.200000 79.360000 ;
    END
  END cp_ctrl[59]
  PIN cp_ctrl[58]
    DIRECTION OUTPUT ;
    USE SIGNAL ;
    PORT
      LAYER M4 ;
        RECT 0.000000 80.140000 0.200000 80.340000 ;
    END
  END cp_ctrl[58]
  PIN cp_ctrl[57]
    DIRECTION OUTPUT ;
    USE SIGNAL ;
    PORT
      LAYER M4 ;
        RECT 0.000000 81.120000 0.200000 81.320000 ;
    END
  END cp_ctrl[57]
  PIN cp_ctrl[56]
    DIRECTION OUTPUT ;
    USE SIGNAL ;
    PORT
      LAYER M4 ;
        RECT 0.000000 83.080000 0.200000 83.280000 ;
    END
  END cp_ctrl[56]
  PIN cp_ctrl[55]
    DIRECTION OUTPUT ;
    USE SIGNAL ;
    PORT
      LAYER M4 ;
        RECT 0.000000 84.060000 0.200000 84.260000 ;
    END
  END cp_ctrl[55]
  PIN cp_ctrl[54]
    DIRECTION OUTPUT ;
    USE SIGNAL ;
    PORT
      LAYER M4 ;
        RECT 0.000000 85.040000 0.200000 85.240000 ;
    END
  END cp_ctrl[54]
  PIN cp_ctrl[53]
    DIRECTION OUTPUT ;
    USE SIGNAL ;
    PORT
      LAYER M4 ;
        RECT 0.000000 86.020000 0.200000 86.220000 ;
    END
  END cp_ctrl[53]
  PIN cp_ctrl[52]
    DIRECTION OUTPUT ;
    USE SIGNAL ;
    PORT
      LAYER M4 ;
        RECT 0.000000 87.000000 0.200000 87.200000 ;
    END
  END cp_ctrl[52]
  PIN cp_ctrl[51]
    DIRECTION OUTPUT ;
    USE SIGNAL ;
    PORT
      LAYER M4 ;
        RECT 0.000000 87.980000 0.200000 88.180000 ;
    END
  END cp_ctrl[51]
  PIN cp_ctrl[50]
    DIRECTION OUTPUT ;
    USE SIGNAL ;
    PORT
      LAYER M4 ;
        RECT 0.000000 88.960000 0.200000 89.160000 ;
    END
  END cp_ctrl[50]
  PIN cp_ctrl[49]
    DIRECTION OUTPUT ;
    USE SIGNAL ;
    PORT
      LAYER M4 ;
        RECT 0.000000 89.940000 0.200000 90.140000 ;
    END
  END cp_ctrl[49]
  PIN cp_ctrl[48]
    DIRECTION OUTPUT ;
    USE SIGNAL ;
    PORT
      LAYER M4 ;
        RECT 0.000000 90.920000 0.200000 91.120000 ;
    END
  END cp_ctrl[48]
  PIN cp_ctrl[47]
    DIRECTION OUTPUT ;
    USE SIGNAL ;
    PORT
      LAYER M4 ;
        RECT 0.000000 91.900000 0.200000 92.100000 ;
    END
  END cp_ctrl[47]
  PIN cp_ctrl[46]
    DIRECTION OUTPUT ;
    USE SIGNAL ;
    PORT
      LAYER M4 ;
        RECT 0.000000 92.880000 0.200000 93.080000 ;
    END
  END cp_ctrl[46]
  PIN cp_ctrl[45]
    DIRECTION OUTPUT ;
    USE SIGNAL ;
    PORT
      LAYER M4 ;
        RECT 0.000000 93.860000 0.200000 94.060000 ;
    END
  END cp_ctrl[45]
  PIN cp_ctrl[44]
    DIRECTION OUTPUT ;
    USE SIGNAL ;
    PORT
      LAYER M4 ;
        RECT 0.000000 94.840000 0.200000 95.040000 ;
    END
  END cp_ctrl[44]
  PIN cp_ctrl[43]
    DIRECTION OUTPUT ;
    USE SIGNAL ;
    PORT
      LAYER M4 ;
        RECT 0.000000 95.820000 0.200000 96.020000 ;
    END
  END cp_ctrl[43]
  PIN cp_ctrl[42]
    DIRECTION OUTPUT ;
    USE SIGNAL ;
    PORT
      LAYER M4 ;
        RECT 0.000000 96.800000 0.200000 97.000000 ;
    END
  END cp_ctrl[42]
  PIN cp_ctrl[41]
    DIRECTION OUTPUT ;
    USE SIGNAL ;
    PORT
      LAYER M4 ;
        RECT 0.000000 18.950000 0.200000 19.150000 ;
    END
  END cp_ctrl[41]
  PIN cp_ctrl[40]
    DIRECTION OUTPUT ;
    USE SIGNAL ;
    PORT
      LAYER M4 ;
        RECT 0.000000 33.650000 0.200000 33.850000 ;
    END
  END cp_ctrl[40]
  PIN cp_ctrl[39]
    DIRECTION OUTPUT ;
    USE SIGNAL ;
    PORT
      LAYER M4 ;
        RECT 0.000000 6.210000 0.200000 6.410000 ;
    END
  END cp_ctrl[39]
  PIN cp_ctrl[38]
    DIRECTION OUTPUT ;
    USE SIGNAL ;
    PORT
      LAYER M4 ;
        RECT 0.000000 7.190000 0.200000 7.390000 ;
    END
  END cp_ctrl[38]
  PIN cp_ctrl[37]
    DIRECTION OUTPUT ;
    USE SIGNAL ;
    PORT
      LAYER M4 ;
        RECT 0.000000 8.170000 0.200000 8.370000 ;
    END
  END cp_ctrl[37]
  PIN cp_ctrl[36]
    DIRECTION OUTPUT ;
    USE SIGNAL ;
    PORT
      LAYER M4 ;
        RECT 0.000000 9.150000 0.200000 9.350000 ;
    END
  END cp_ctrl[36]
  PIN cp_ctrl[35]
    DIRECTION OUTPUT ;
    USE SIGNAL ;
    PORT
      LAYER M4 ;
        RECT 0.000000 10.130000 0.200000 10.330000 ;
    END
  END cp_ctrl[35]
  PIN cp_ctrl[34]
    DIRECTION OUTPUT ;
    USE SIGNAL ;
    PORT
      LAYER M4 ;
        RECT 0.000000 11.110000 0.200000 11.310000 ;
    END
  END cp_ctrl[34]
  PIN cp_ctrl[33]
    DIRECTION OUTPUT ;
    USE SIGNAL ;
    PORT
      LAYER M4 ;
        RECT 0.000000 12.090000 0.200000 12.290000 ;
    END
  END cp_ctrl[33]
  PIN cp_ctrl[32]
    DIRECTION OUTPUT ;
    USE SIGNAL ;
    PORT
      LAYER M4 ;
        RECT 0.000000 15.030000 0.200000 15.230000 ;
    END
  END cp_ctrl[32]
  PIN cp_ctrl[31]
    DIRECTION OUTPUT ;
    USE SIGNAL ;
    PORT
      LAYER M4 ;
        RECT 0.000000 16.010000 0.200000 16.210000 ;
    END
  END cp_ctrl[31]
  PIN cp_ctrl[30]
    DIRECTION OUTPUT ;
    USE SIGNAL ;
    PORT
      LAYER M4 ;
        RECT 0.000000 16.990000 0.200000 17.190000 ;
    END
  END cp_ctrl[30]
  PIN cp_ctrl[29]
    DIRECTION OUTPUT ;
    USE SIGNAL ;
    PORT
      LAYER M4 ;
        RECT 0.000000 17.970000 0.200000 18.170000 ;
    END
  END cp_ctrl[29]
  PIN cp_ctrl[28]
    DIRECTION OUTPUT ;
    USE SIGNAL ;
    PORT
      LAYER M4 ;
        RECT 0.000000 19.930000 0.200000 20.130000 ;
    END
  END cp_ctrl[28]
  PIN cp_ctrl[27]
    DIRECTION OUTPUT ;
    USE SIGNAL ;
    PORT
      LAYER M4 ;
        RECT 0.000000 20.910000 0.200000 21.110000 ;
    END
  END cp_ctrl[27]
  PIN cp_ctrl[26]
    DIRECTION OUTPUT ;
    USE SIGNAL ;
    PORT
      LAYER M4 ;
        RECT 0.000000 21.890000 0.200000 22.090000 ;
    END
  END cp_ctrl[26]
  PIN cp_ctrl[25]
    DIRECTION OUTPUT ;
    USE SIGNAL ;
    PORT
      LAYER M4 ;
        RECT 0.000000 22.870000 0.200000 23.070000 ;
    END
  END cp_ctrl[25]
  PIN cp_ctrl[24]
    DIRECTION OUTPUT ;
    USE SIGNAL ;
    PORT
      LAYER M4 ;
        RECT 0.000000 23.850000 0.200000 24.050000 ;
    END
  END cp_ctrl[24]
  PIN cp_ctrl[23]
    DIRECTION OUTPUT ;
    USE SIGNAL ;
    PORT
      LAYER M4 ;
        RECT 0.000000 24.830000 0.200000 25.030000 ;
    END
  END cp_ctrl[23]
  PIN cp_ctrl[22]
    DIRECTION OUTPUT ;
    USE SIGNAL ;
    PORT
      LAYER M4 ;
        RECT 0.000000 25.810000 0.200000 26.010000 ;
    END
  END cp_ctrl[22]
  PIN cp_ctrl[21]
    DIRECTION OUTPUT ;
    USE SIGNAL ;
    PORT
      LAYER M4 ;
        RECT 0.000000 26.790000 0.200000 26.990000 ;
    END
  END cp_ctrl[21]
  PIN cp_ctrl[20]
    DIRECTION OUTPUT ;
    USE SIGNAL ;
    PORT
      LAYER M4 ;
        RECT 0.000000 27.770000 0.200000 27.970000 ;
    END
  END cp_ctrl[20]
  PIN cp_ctrl[19]
    DIRECTION OUTPUT ;
    USE SIGNAL ;
    PORT
      LAYER M4 ;
        RECT 0.000000 28.750000 0.200000 28.950000 ;
    END
  END cp_ctrl[19]
  PIN cp_ctrl[18]
    DIRECTION OUTPUT ;
    USE SIGNAL ;
    PORT
      LAYER M4 ;
        RECT 0.000000 29.730000 0.200000 29.930000 ;
    END
  END cp_ctrl[18]
  PIN cp_ctrl[17]
    DIRECTION OUTPUT ;
    USE SIGNAL ;
    PORT
      LAYER M4 ;
        RECT 0.000000 30.710000 0.200000 30.910000 ;
    END
  END cp_ctrl[17]
  PIN cp_ctrl[16]
    DIRECTION OUTPUT ;
    USE SIGNAL ;
    PORT
      LAYER M4 ;
        RECT 0.000000 31.690000 0.200000 31.890000 ;
    END
  END cp_ctrl[16]
  PIN cp_ctrl[15]
    DIRECTION OUTPUT ;
    USE SIGNAL ;
    PORT
      LAYER M4 ;
        RECT 0.000000 32.670000 0.200000 32.870000 ;
    END
  END cp_ctrl[15]
  PIN cp_ctrl[14]
    DIRECTION OUTPUT ;
    USE SIGNAL ;
    PORT
      LAYER M4 ;
        RECT 0.000000 34.630000 0.200000 34.830000 ;
    END
  END cp_ctrl[14]
  PIN cp_ctrl[13]
    DIRECTION OUTPUT ;
    USE SIGNAL ;
    PORT
      LAYER M4 ;
        RECT 0.000000 35.610000 0.200000 35.810000 ;
    END
  END cp_ctrl[13]
  PIN cp_ctrl[12]
    DIRECTION OUTPUT ;
    USE SIGNAL ;
    PORT
      LAYER M4 ;
        RECT 0.000000 36.590000 0.200000 36.790000 ;
    END
  END cp_ctrl[12]
  PIN cp_ctrl[11]
    DIRECTION OUTPUT ;
    USE SIGNAL ;
    PORT
      LAYER M4 ;
        RECT 0.000000 37.570000 0.200000 37.770000 ;
    END
  END cp_ctrl[11]
  PIN cp_ctrl[10]
    DIRECTION OUTPUT ;
    USE SIGNAL ;
    PORT
      LAYER M4 ;
        RECT 0.000000 38.550000 0.200000 38.750000 ;
    END
  END cp_ctrl[10]
  PIN cp_ctrl[9]
    DIRECTION OUTPUT ;
    USE SIGNAL ;
    PORT
      LAYER M4 ;
        RECT 0.000000 39.530000 0.200000 39.730000 ;
    END
  END cp_ctrl[9]
  PIN cp_ctrl[8]
    DIRECTION OUTPUT ;
    USE SIGNAL ;
    PORT
      LAYER M4 ;
        RECT 0.000000 40.510000 0.200000 40.710000 ;
    END
  END cp_ctrl[8]
  PIN cp_ctrl[7]
    DIRECTION OUTPUT ;
    USE SIGNAL ;
    PORT
      LAYER M4 ;
        RECT 0.000000 41.490000 0.200000 41.690000 ;
    END
  END cp_ctrl[7]
  PIN cp_ctrl[6]
    DIRECTION OUTPUT ;
    USE SIGNAL ;
    PORT
      LAYER M4 ;
        RECT 0.000000 42.470000 0.200000 42.670000 ;
    END
  END cp_ctrl[6]
  PIN cp_ctrl[5]
    DIRECTION OUTPUT ;
    USE SIGNAL ;
    PORT
      LAYER M4 ;
        RECT 0.000000 43.450000 0.200000 43.650000 ;
    END
  END cp_ctrl[5]
  PIN cp_ctrl[4]
    DIRECTION OUTPUT ;
    USE SIGNAL ;
    PORT
      LAYER M4 ;
        RECT 0.000000 44.430000 0.200000 44.630000 ;
    END
  END cp_ctrl[4]
  PIN cp_ctrl[3]
    DIRECTION OUTPUT ;
    USE SIGNAL ;
    PORT
      LAYER M4 ;
        RECT 0.000000 45.410000 0.200000 45.610000 ;
    END
  END cp_ctrl[3]
  PIN cp_ctrl[2]
    DIRECTION OUTPUT ;
    USE SIGNAL ;
    PORT
      LAYER M4 ;
        RECT 0.000000 46.390000 0.200000 46.590000 ;
    END
  END cp_ctrl[2]
  PIN cp_ctrl[1]
    DIRECTION OUTPUT ;
    USE SIGNAL ;
    PORT
      LAYER M4 ;
        RECT 0.000000 47.370000 0.200000 47.570000 ;
    END
  END cp_ctrl[1]
  PIN cp_ctrl[0]
    DIRECTION OUTPUT ;
    USE SIGNAL ;
    PORT
      LAYER M4 ;
        RECT 0.000000 48.350000 0.200000 48.550000 ;
    END
  END cp_ctrl[0]
  PIN rd_vld
    DIRECTION OUTPUT ;
    USE SIGNAL ;
    PORT
      LAYER M4 ;
        RECT 6.400000 488.300000 6.600000 488.500000 ;
    END
  END rd_vld
  PIN rd_data_out
    DIRECTION OUTPUT ;
    USE SIGNAL ;
    PORT
      LAYER M4 ;
        RECT 7.500000 488.300000 7.700000 488.500000 ;
    END
  END rd_data_out
  PIN p_out_vld
    DIRECTION OUTPUT ;
    USE SIGNAL ;
    PORT
      LAYER M4 ;
        RECT 9.700000 488.300000 9.900000 488.500000 ;
    END
  END p_out_vld
  PIN p_out
    DIRECTION OUTPUT ;
    USE SIGNAL ;
    PORT
      LAYER M4 ;
        RECT 10.800000 488.300000 11.000000 488.500000 ;
    END
  END p_out
  OBS
    LAYER M1 ;
      RECT 0.000000 0.000000 16.000000 488.500000 ;
    LAYER M2 ;
      RECT 0.000000 0.000000 16.000000 488.500000 ;
    LAYER M3 ;
      RECT 0.000000 0.000000 16.000000 488.500000 ;
    LAYER M4 ;
      RECT 11.100000 488.200000 16.000000 488.500000 ;
      RECT 10.000000 488.200000 10.700000 488.500000 ;
      RECT 8.900000 488.200000 9.600000 488.500000 ;
      RECT 7.800000 488.200000 8.500000 488.500000 ;
      RECT 6.700000 488.200000 7.400000 488.500000 ;
      RECT 5.600000 488.200000 6.300000 488.500000 ;
      RECT 4.500000 488.200000 5.200000 488.500000 ;
      RECT 3.400000 488.200000 4.100000 488.500000 ;
      RECT 2.300000 488.200000 3.000000 488.500000 ;
      RECT 1.200000 488.200000 1.900000 488.500000 ;
      RECT 0.000000 488.200000 0.800000 488.500000 ;
      RECT 0.000000 484.700000 16.000000 488.200000 ;
      RECT 0.300000 484.300000 16.000000 484.700000 ;
      RECT 0.000000 483.720000 16.000000 484.300000 ;
      RECT 0.300000 483.320000 16.000000 483.720000 ;
      RECT 0.000000 482.740000 16.000000 483.320000 ;
      RECT 0.300000 482.340000 16.000000 482.740000 ;
      RECT 0.000000 481.760000 16.000000 482.340000 ;
      RECT 0.300000 481.360000 16.000000 481.760000 ;
      RECT 0.000000 480.780000 16.000000 481.360000 ;
      RECT 0.300000 480.380000 16.000000 480.780000 ;
      RECT 0.000000 479.800000 16.000000 480.380000 ;
      RECT 0.300000 479.400000 16.000000 479.800000 ;
      RECT 0.000000 478.820000 16.000000 479.400000 ;
      RECT 0.300000 478.420000 16.000000 478.820000 ;
      RECT 0.000000 477.840000 16.000000 478.420000 ;
      RECT 0.300000 477.440000 16.000000 477.840000 ;
      RECT 0.000000 476.860000 16.000000 477.440000 ;
      RECT 0.300000 476.460000 16.000000 476.860000 ;
      RECT 0.000000 475.880000 16.000000 476.460000 ;
      RECT 0.300000 475.480000 16.000000 475.880000 ;
      RECT 0.000000 474.900000 16.000000 475.480000 ;
      RECT 0.300000 474.500000 16.000000 474.900000 ;
      RECT 0.000000 473.920000 16.000000 474.500000 ;
      RECT 0.300000 473.520000 16.000000 473.920000 ;
      RECT 0.000000 472.940000 16.000000 473.520000 ;
      RECT 0.300000 472.540000 16.000000 472.940000 ;
      RECT 0.000000 471.960000 16.000000 472.540000 ;
      RECT 0.300000 471.560000 16.000000 471.960000 ;
      RECT 0.000000 470.980000 16.000000 471.560000 ;
      RECT 0.300000 470.580000 16.000000 470.980000 ;
      RECT 0.000000 470.000000 16.000000 470.580000 ;
      RECT 0.300000 469.600000 16.000000 470.000000 ;
      RECT 0.000000 469.020000 16.000000 469.600000 ;
      RECT 0.300000 468.620000 16.000000 469.020000 ;
      RECT 0.000000 468.040000 16.000000 468.620000 ;
      RECT 0.300000 467.640000 16.000000 468.040000 ;
      RECT 0.000000 467.060000 16.000000 467.640000 ;
      RECT 0.300000 466.660000 16.000000 467.060000 ;
      RECT 0.000000 466.080000 16.000000 466.660000 ;
      RECT 0.300000 465.680000 16.000000 466.080000 ;
      RECT 0.000000 465.100000 16.000000 465.680000 ;
      RECT 0.300000 464.700000 16.000000 465.100000 ;
      RECT 0.000000 464.120000 16.000000 464.700000 ;
      RECT 0.300000 463.720000 16.000000 464.120000 ;
      RECT 0.000000 463.140000 16.000000 463.720000 ;
      RECT 0.300000 462.740000 16.000000 463.140000 ;
      RECT 0.000000 462.160000 16.000000 462.740000 ;
      RECT 0.300000 461.760000 16.000000 462.160000 ;
      RECT 0.000000 461.180000 16.000000 461.760000 ;
      RECT 0.300000 460.780000 16.000000 461.180000 ;
      RECT 0.000000 460.200000 16.000000 460.780000 ;
      RECT 0.300000 459.800000 16.000000 460.200000 ;
      RECT 0.000000 459.220000 16.000000 459.800000 ;
      RECT 0.300000 458.820000 16.000000 459.220000 ;
      RECT 0.000000 458.240000 16.000000 458.820000 ;
      RECT 0.300000 457.840000 16.000000 458.240000 ;
      RECT 0.000000 457.260000 16.000000 457.840000 ;
      RECT 0.300000 456.860000 16.000000 457.260000 ;
      RECT 0.000000 456.280000 16.000000 456.860000 ;
      RECT 0.300000 455.880000 16.000000 456.280000 ;
      RECT 0.000000 455.300000 16.000000 455.880000 ;
      RECT 0.300000 454.900000 16.000000 455.300000 ;
      RECT 0.000000 454.320000 16.000000 454.900000 ;
      RECT 0.300000 453.920000 16.000000 454.320000 ;
      RECT 0.000000 453.340000 16.000000 453.920000 ;
      RECT 0.300000 452.940000 16.000000 453.340000 ;
      RECT 0.000000 452.360000 16.000000 452.940000 ;
      RECT 0.300000 451.960000 16.000000 452.360000 ;
      RECT 0.000000 451.380000 16.000000 451.960000 ;
      RECT 0.300000 450.980000 16.000000 451.380000 ;
      RECT 0.000000 450.400000 16.000000 450.980000 ;
      RECT 0.300000 450.000000 16.000000 450.400000 ;
      RECT 0.000000 449.420000 16.000000 450.000000 ;
      RECT 0.300000 449.020000 16.000000 449.420000 ;
      RECT 0.000000 448.440000 16.000000 449.020000 ;
      RECT 0.300000 448.040000 16.000000 448.440000 ;
      RECT 0.000000 447.460000 16.000000 448.040000 ;
      RECT 0.300000 447.060000 16.000000 447.460000 ;
      RECT 0.000000 446.480000 16.000000 447.060000 ;
      RECT 0.300000 446.080000 16.000000 446.480000 ;
      RECT 0.000000 445.500000 16.000000 446.080000 ;
      RECT 0.300000 445.100000 16.000000 445.500000 ;
      RECT 0.000000 444.520000 16.000000 445.100000 ;
      RECT 0.300000 444.120000 16.000000 444.520000 ;
      RECT 0.000000 443.540000 16.000000 444.120000 ;
      RECT 0.300000 443.140000 16.000000 443.540000 ;
      RECT 0.000000 442.560000 16.000000 443.140000 ;
      RECT 0.300000 442.160000 16.000000 442.560000 ;
      RECT 0.000000 436.250000 16.000000 442.160000 ;
      RECT 0.300000 435.850000 16.000000 436.250000 ;
      RECT 0.000000 435.270000 16.000000 435.850000 ;
      RECT 0.300000 434.870000 16.000000 435.270000 ;
      RECT 0.000000 434.290000 16.000000 434.870000 ;
      RECT 0.300000 433.890000 16.000000 434.290000 ;
      RECT 0.000000 433.310000 16.000000 433.890000 ;
      RECT 0.300000 432.910000 16.000000 433.310000 ;
      RECT 0.000000 432.330000 16.000000 432.910000 ;
      RECT 0.300000 431.930000 16.000000 432.330000 ;
      RECT 0.000000 431.350000 16.000000 431.930000 ;
      RECT 0.300000 430.950000 16.000000 431.350000 ;
      RECT 0.000000 430.370000 16.000000 430.950000 ;
      RECT 0.300000 429.970000 16.000000 430.370000 ;
      RECT 0.000000 429.390000 16.000000 429.970000 ;
      RECT 0.300000 428.990000 16.000000 429.390000 ;
      RECT 0.000000 428.410000 16.000000 428.990000 ;
      RECT 0.300000 428.010000 16.000000 428.410000 ;
      RECT 0.000000 427.430000 16.000000 428.010000 ;
      RECT 0.300000 427.030000 16.000000 427.430000 ;
      RECT 0.000000 426.450000 16.000000 427.030000 ;
      RECT 0.300000 426.050000 16.000000 426.450000 ;
      RECT 0.000000 425.470000 16.000000 426.050000 ;
      RECT 0.300000 425.070000 16.000000 425.470000 ;
      RECT 0.000000 424.490000 16.000000 425.070000 ;
      RECT 0.300000 424.090000 16.000000 424.490000 ;
      RECT 0.000000 423.510000 16.000000 424.090000 ;
      RECT 0.300000 423.110000 16.000000 423.510000 ;
      RECT 0.000000 422.530000 16.000000 423.110000 ;
      RECT 0.300000 422.130000 16.000000 422.530000 ;
      RECT 0.000000 421.550000 16.000000 422.130000 ;
      RECT 0.300000 421.150000 16.000000 421.550000 ;
      RECT 0.000000 420.570000 16.000000 421.150000 ;
      RECT 0.300000 420.170000 16.000000 420.570000 ;
      RECT 0.000000 419.590000 16.000000 420.170000 ;
      RECT 0.300000 419.190000 16.000000 419.590000 ;
      RECT 0.000000 418.610000 16.000000 419.190000 ;
      RECT 0.300000 418.210000 16.000000 418.610000 ;
      RECT 0.000000 417.630000 16.000000 418.210000 ;
      RECT 0.300000 417.230000 16.000000 417.630000 ;
      RECT 0.000000 416.650000 16.000000 417.230000 ;
      RECT 0.300000 416.250000 16.000000 416.650000 ;
      RECT 0.000000 415.670000 16.000000 416.250000 ;
      RECT 0.300000 415.270000 16.000000 415.670000 ;
      RECT 0.000000 414.690000 16.000000 415.270000 ;
      RECT 0.300000 414.290000 16.000000 414.690000 ;
      RECT 0.000000 413.710000 16.000000 414.290000 ;
      RECT 0.300000 413.310000 16.000000 413.710000 ;
      RECT 0.000000 412.730000 16.000000 413.310000 ;
      RECT 0.300000 412.330000 16.000000 412.730000 ;
      RECT 0.000000 411.750000 16.000000 412.330000 ;
      RECT 0.300000 411.350000 16.000000 411.750000 ;
      RECT 0.000000 410.770000 16.000000 411.350000 ;
      RECT 0.300000 410.370000 16.000000 410.770000 ;
      RECT 0.000000 409.790000 16.000000 410.370000 ;
      RECT 0.300000 409.390000 16.000000 409.790000 ;
      RECT 0.000000 408.810000 16.000000 409.390000 ;
      RECT 0.300000 408.410000 16.000000 408.810000 ;
      RECT 0.000000 407.830000 16.000000 408.410000 ;
      RECT 0.300000 407.430000 16.000000 407.830000 ;
      RECT 0.000000 406.850000 16.000000 407.430000 ;
      RECT 0.300000 406.450000 16.000000 406.850000 ;
      RECT 0.000000 405.870000 16.000000 406.450000 ;
      RECT 0.300000 405.470000 16.000000 405.870000 ;
      RECT 0.000000 404.890000 16.000000 405.470000 ;
      RECT 0.300000 404.490000 16.000000 404.890000 ;
      RECT 0.000000 403.910000 16.000000 404.490000 ;
      RECT 0.300000 403.510000 16.000000 403.910000 ;
      RECT 0.000000 402.930000 16.000000 403.510000 ;
      RECT 0.300000 402.530000 16.000000 402.930000 ;
      RECT 0.000000 401.950000 16.000000 402.530000 ;
      RECT 0.300000 401.550000 16.000000 401.950000 ;
      RECT 0.000000 400.970000 16.000000 401.550000 ;
      RECT 0.300000 400.570000 16.000000 400.970000 ;
      RECT 0.000000 399.990000 16.000000 400.570000 ;
      RECT 0.300000 399.590000 16.000000 399.990000 ;
      RECT 0.000000 399.010000 16.000000 399.590000 ;
      RECT 0.300000 398.610000 16.000000 399.010000 ;
      RECT 0.000000 398.030000 16.000000 398.610000 ;
      RECT 0.300000 397.630000 16.000000 398.030000 ;
      RECT 0.000000 397.050000 16.000000 397.630000 ;
      RECT 0.300000 396.650000 16.000000 397.050000 ;
      RECT 0.000000 396.070000 16.000000 396.650000 ;
      RECT 0.300000 395.670000 16.000000 396.070000 ;
      RECT 0.000000 395.090000 16.000000 395.670000 ;
      RECT 0.300000 394.690000 16.000000 395.090000 ;
      RECT 0.000000 394.110000 16.000000 394.690000 ;
      RECT 0.300000 393.710000 16.000000 394.110000 ;
      RECT 0.000000 387.800000 16.000000 393.710000 ;
      RECT 0.300000 387.400000 16.000000 387.800000 ;
      RECT 0.000000 386.820000 16.000000 387.400000 ;
      RECT 0.300000 386.420000 16.000000 386.820000 ;
      RECT 0.000000 385.840000 16.000000 386.420000 ;
      RECT 0.300000 385.440000 16.000000 385.840000 ;
      RECT 0.000000 384.860000 16.000000 385.440000 ;
      RECT 0.300000 384.460000 16.000000 384.860000 ;
      RECT 0.000000 383.880000 16.000000 384.460000 ;
      RECT 0.300000 383.480000 16.000000 383.880000 ;
      RECT 0.000000 382.900000 16.000000 383.480000 ;
      RECT 0.300000 382.500000 16.000000 382.900000 ;
      RECT 0.000000 381.920000 16.000000 382.500000 ;
      RECT 0.300000 381.520000 16.000000 381.920000 ;
      RECT 0.000000 380.940000 16.000000 381.520000 ;
      RECT 0.300000 380.540000 16.000000 380.940000 ;
      RECT 0.000000 379.960000 16.000000 380.540000 ;
      RECT 0.300000 379.560000 16.000000 379.960000 ;
      RECT 0.000000 378.980000 16.000000 379.560000 ;
      RECT 0.300000 378.580000 16.000000 378.980000 ;
      RECT 0.000000 378.000000 16.000000 378.580000 ;
      RECT 0.300000 377.600000 16.000000 378.000000 ;
      RECT 0.000000 377.020000 16.000000 377.600000 ;
      RECT 0.300000 376.620000 16.000000 377.020000 ;
      RECT 0.000000 376.040000 16.000000 376.620000 ;
      RECT 0.300000 375.640000 16.000000 376.040000 ;
      RECT 0.000000 375.060000 16.000000 375.640000 ;
      RECT 0.300000 374.660000 16.000000 375.060000 ;
      RECT 0.000000 374.080000 16.000000 374.660000 ;
      RECT 0.300000 373.680000 16.000000 374.080000 ;
      RECT 0.000000 373.100000 16.000000 373.680000 ;
      RECT 0.300000 372.700000 16.000000 373.100000 ;
      RECT 0.000000 372.120000 16.000000 372.700000 ;
      RECT 0.300000 371.720000 16.000000 372.120000 ;
      RECT 0.000000 371.140000 16.000000 371.720000 ;
      RECT 0.300000 370.740000 16.000000 371.140000 ;
      RECT 0.000000 370.160000 16.000000 370.740000 ;
      RECT 0.300000 369.760000 16.000000 370.160000 ;
      RECT 0.000000 369.180000 16.000000 369.760000 ;
      RECT 0.300000 368.780000 16.000000 369.180000 ;
      RECT 0.000000 368.200000 16.000000 368.780000 ;
      RECT 0.300000 367.800000 16.000000 368.200000 ;
      RECT 0.000000 367.220000 16.000000 367.800000 ;
      RECT 0.300000 366.820000 16.000000 367.220000 ;
      RECT 0.000000 366.240000 16.000000 366.820000 ;
      RECT 0.300000 365.840000 16.000000 366.240000 ;
      RECT 0.000000 365.260000 16.000000 365.840000 ;
      RECT 0.300000 364.860000 16.000000 365.260000 ;
      RECT 0.000000 364.280000 16.000000 364.860000 ;
      RECT 0.300000 363.880000 16.000000 364.280000 ;
      RECT 0.000000 363.300000 16.000000 363.880000 ;
      RECT 0.300000 362.900000 16.000000 363.300000 ;
      RECT 0.000000 362.320000 16.000000 362.900000 ;
      RECT 0.300000 361.920000 16.000000 362.320000 ;
      RECT 0.000000 361.340000 16.000000 361.920000 ;
      RECT 0.300000 360.940000 16.000000 361.340000 ;
      RECT 0.000000 360.360000 16.000000 360.940000 ;
      RECT 0.300000 359.960000 16.000000 360.360000 ;
      RECT 0.000000 359.380000 16.000000 359.960000 ;
      RECT 0.300000 358.980000 16.000000 359.380000 ;
      RECT 0.000000 358.400000 16.000000 358.980000 ;
      RECT 0.300000 358.000000 16.000000 358.400000 ;
      RECT 0.000000 357.420000 16.000000 358.000000 ;
      RECT 0.300000 357.020000 16.000000 357.420000 ;
      RECT 0.000000 356.440000 16.000000 357.020000 ;
      RECT 0.300000 356.040000 16.000000 356.440000 ;
      RECT 0.000000 355.460000 16.000000 356.040000 ;
      RECT 0.300000 355.060000 16.000000 355.460000 ;
      RECT 0.000000 354.480000 16.000000 355.060000 ;
      RECT 0.300000 354.080000 16.000000 354.480000 ;
      RECT 0.000000 353.500000 16.000000 354.080000 ;
      RECT 0.300000 353.100000 16.000000 353.500000 ;
      RECT 0.000000 352.520000 16.000000 353.100000 ;
      RECT 0.300000 352.120000 16.000000 352.520000 ;
      RECT 0.000000 351.540000 16.000000 352.120000 ;
      RECT 0.300000 351.140000 16.000000 351.540000 ;
      RECT 0.000000 350.560000 16.000000 351.140000 ;
      RECT 0.300000 350.160000 16.000000 350.560000 ;
      RECT 0.000000 349.580000 16.000000 350.160000 ;
      RECT 0.300000 349.180000 16.000000 349.580000 ;
      RECT 0.000000 348.600000 16.000000 349.180000 ;
      RECT 0.300000 348.200000 16.000000 348.600000 ;
      RECT 0.000000 347.620000 16.000000 348.200000 ;
      RECT 0.300000 347.220000 16.000000 347.620000 ;
      RECT 0.000000 346.640000 16.000000 347.220000 ;
      RECT 0.300000 346.240000 16.000000 346.640000 ;
      RECT 0.000000 345.660000 16.000000 346.240000 ;
      RECT 0.300000 345.260000 16.000000 345.660000 ;
      RECT 0.000000 339.350000 16.000000 345.260000 ;
      RECT 0.300000 338.950000 16.000000 339.350000 ;
      RECT 0.000000 338.370000 16.000000 338.950000 ;
      RECT 0.300000 337.970000 16.000000 338.370000 ;
      RECT 0.000000 337.390000 16.000000 337.970000 ;
      RECT 0.300000 336.990000 16.000000 337.390000 ;
      RECT 0.000000 336.410000 16.000000 336.990000 ;
      RECT 0.300000 336.010000 16.000000 336.410000 ;
      RECT 0.000000 335.430000 16.000000 336.010000 ;
      RECT 0.300000 335.030000 16.000000 335.430000 ;
      RECT 0.000000 334.450000 16.000000 335.030000 ;
      RECT 0.300000 334.050000 16.000000 334.450000 ;
      RECT 0.000000 333.470000 16.000000 334.050000 ;
      RECT 0.300000 333.070000 16.000000 333.470000 ;
      RECT 0.000000 332.490000 16.000000 333.070000 ;
      RECT 0.300000 332.090000 16.000000 332.490000 ;
      RECT 0.000000 331.510000 16.000000 332.090000 ;
      RECT 0.300000 331.110000 16.000000 331.510000 ;
      RECT 0.000000 330.530000 16.000000 331.110000 ;
      RECT 0.300000 330.130000 16.000000 330.530000 ;
      RECT 0.000000 329.550000 16.000000 330.130000 ;
      RECT 0.300000 329.150000 16.000000 329.550000 ;
      RECT 0.000000 328.570000 16.000000 329.150000 ;
      RECT 0.300000 328.170000 16.000000 328.570000 ;
      RECT 0.000000 327.590000 16.000000 328.170000 ;
      RECT 0.300000 327.190000 16.000000 327.590000 ;
      RECT 0.000000 326.610000 16.000000 327.190000 ;
      RECT 0.300000 326.210000 16.000000 326.610000 ;
      RECT 0.000000 325.630000 16.000000 326.210000 ;
      RECT 0.300000 325.230000 16.000000 325.630000 ;
      RECT 0.000000 324.650000 16.000000 325.230000 ;
      RECT 0.300000 324.250000 16.000000 324.650000 ;
      RECT 0.000000 323.670000 16.000000 324.250000 ;
      RECT 0.300000 323.270000 16.000000 323.670000 ;
      RECT 0.000000 322.690000 16.000000 323.270000 ;
      RECT 0.300000 322.290000 16.000000 322.690000 ;
      RECT 0.000000 321.710000 16.000000 322.290000 ;
      RECT 0.300000 321.310000 16.000000 321.710000 ;
      RECT 0.000000 320.730000 16.000000 321.310000 ;
      RECT 0.300000 320.330000 16.000000 320.730000 ;
      RECT 0.000000 319.750000 16.000000 320.330000 ;
      RECT 0.300000 319.350000 16.000000 319.750000 ;
      RECT 0.000000 318.770000 16.000000 319.350000 ;
      RECT 0.300000 318.370000 16.000000 318.770000 ;
      RECT 0.000000 317.790000 16.000000 318.370000 ;
      RECT 0.300000 317.390000 16.000000 317.790000 ;
      RECT 0.000000 316.810000 16.000000 317.390000 ;
      RECT 0.300000 316.410000 16.000000 316.810000 ;
      RECT 0.000000 315.830000 16.000000 316.410000 ;
      RECT 0.300000 315.430000 16.000000 315.830000 ;
      RECT 0.000000 314.850000 16.000000 315.430000 ;
      RECT 0.300000 314.450000 16.000000 314.850000 ;
      RECT 0.000000 313.870000 16.000000 314.450000 ;
      RECT 0.300000 313.470000 16.000000 313.870000 ;
      RECT 0.000000 312.890000 16.000000 313.470000 ;
      RECT 0.300000 312.490000 16.000000 312.890000 ;
      RECT 0.000000 311.910000 16.000000 312.490000 ;
      RECT 0.300000 311.510000 16.000000 311.910000 ;
      RECT 0.000000 310.930000 16.000000 311.510000 ;
      RECT 0.300000 310.530000 16.000000 310.930000 ;
      RECT 0.000000 309.950000 16.000000 310.530000 ;
      RECT 0.300000 309.550000 16.000000 309.950000 ;
      RECT 0.000000 308.970000 16.000000 309.550000 ;
      RECT 0.300000 308.570000 16.000000 308.970000 ;
      RECT 0.000000 307.990000 16.000000 308.570000 ;
      RECT 0.300000 307.590000 16.000000 307.990000 ;
      RECT 0.000000 307.010000 16.000000 307.590000 ;
      RECT 0.300000 306.610000 16.000000 307.010000 ;
      RECT 0.000000 306.030000 16.000000 306.610000 ;
      RECT 0.300000 305.630000 16.000000 306.030000 ;
      RECT 0.000000 305.050000 16.000000 305.630000 ;
      RECT 0.300000 304.650000 16.000000 305.050000 ;
      RECT 0.000000 304.070000 16.000000 304.650000 ;
      RECT 0.300000 303.670000 16.000000 304.070000 ;
      RECT 0.000000 303.090000 16.000000 303.670000 ;
      RECT 0.300000 302.690000 16.000000 303.090000 ;
      RECT 0.000000 302.110000 16.000000 302.690000 ;
      RECT 0.300000 301.710000 16.000000 302.110000 ;
      RECT 0.000000 301.130000 16.000000 301.710000 ;
      RECT 0.300000 300.730000 16.000000 301.130000 ;
      RECT 0.000000 300.150000 16.000000 300.730000 ;
      RECT 0.300000 299.750000 16.000000 300.150000 ;
      RECT 0.000000 299.170000 16.000000 299.750000 ;
      RECT 0.300000 298.770000 16.000000 299.170000 ;
      RECT 0.000000 298.190000 16.000000 298.770000 ;
      RECT 0.300000 297.790000 16.000000 298.190000 ;
      RECT 0.000000 297.210000 16.000000 297.790000 ;
      RECT 0.300000 296.810000 16.000000 297.210000 ;
      RECT 0.000000 290.900000 16.000000 296.810000 ;
      RECT 0.300000 290.500000 16.000000 290.900000 ;
      RECT 0.000000 289.920000 16.000000 290.500000 ;
      RECT 0.300000 289.520000 16.000000 289.920000 ;
      RECT 0.000000 288.940000 16.000000 289.520000 ;
      RECT 0.300000 288.540000 16.000000 288.940000 ;
      RECT 0.000000 287.960000 16.000000 288.540000 ;
      RECT 0.300000 287.560000 16.000000 287.960000 ;
      RECT 0.000000 286.980000 16.000000 287.560000 ;
      RECT 0.300000 286.580000 16.000000 286.980000 ;
      RECT 0.000000 286.000000 16.000000 286.580000 ;
      RECT 0.300000 285.600000 16.000000 286.000000 ;
      RECT 0.000000 285.020000 16.000000 285.600000 ;
      RECT 0.300000 284.620000 16.000000 285.020000 ;
      RECT 0.000000 284.040000 16.000000 284.620000 ;
      RECT 0.300000 283.640000 16.000000 284.040000 ;
      RECT 0.000000 283.060000 16.000000 283.640000 ;
      RECT 0.300000 282.660000 16.000000 283.060000 ;
      RECT 0.000000 282.080000 16.000000 282.660000 ;
      RECT 0.300000 281.680000 16.000000 282.080000 ;
      RECT 0.000000 281.100000 16.000000 281.680000 ;
      RECT 0.300000 280.700000 16.000000 281.100000 ;
      RECT 0.000000 280.120000 16.000000 280.700000 ;
      RECT 0.300000 279.720000 16.000000 280.120000 ;
      RECT 0.000000 279.140000 16.000000 279.720000 ;
      RECT 0.300000 278.740000 16.000000 279.140000 ;
      RECT 0.000000 278.160000 16.000000 278.740000 ;
      RECT 0.300000 277.760000 16.000000 278.160000 ;
      RECT 0.000000 277.180000 16.000000 277.760000 ;
      RECT 0.300000 276.780000 16.000000 277.180000 ;
      RECT 0.000000 276.200000 16.000000 276.780000 ;
      RECT 0.300000 275.800000 16.000000 276.200000 ;
      RECT 0.000000 275.220000 16.000000 275.800000 ;
      RECT 0.300000 274.820000 16.000000 275.220000 ;
      RECT 0.000000 274.240000 16.000000 274.820000 ;
      RECT 0.300000 273.840000 16.000000 274.240000 ;
      RECT 0.000000 273.260000 16.000000 273.840000 ;
      RECT 0.300000 272.860000 16.000000 273.260000 ;
      RECT 0.000000 272.280000 16.000000 272.860000 ;
      RECT 0.300000 271.880000 16.000000 272.280000 ;
      RECT 0.000000 271.300000 16.000000 271.880000 ;
      RECT 0.300000 270.900000 16.000000 271.300000 ;
      RECT 0.000000 270.320000 16.000000 270.900000 ;
      RECT 0.300000 269.920000 16.000000 270.320000 ;
      RECT 0.000000 269.340000 16.000000 269.920000 ;
      RECT 0.300000 268.940000 16.000000 269.340000 ;
      RECT 0.000000 268.360000 16.000000 268.940000 ;
      RECT 0.300000 267.960000 16.000000 268.360000 ;
      RECT 0.000000 267.380000 16.000000 267.960000 ;
      RECT 0.300000 266.980000 16.000000 267.380000 ;
      RECT 0.000000 266.400000 16.000000 266.980000 ;
      RECT 0.300000 266.000000 16.000000 266.400000 ;
      RECT 0.000000 265.420000 16.000000 266.000000 ;
      RECT 0.300000 265.020000 16.000000 265.420000 ;
      RECT 0.000000 264.440000 16.000000 265.020000 ;
      RECT 0.300000 264.040000 16.000000 264.440000 ;
      RECT 0.000000 263.460000 16.000000 264.040000 ;
      RECT 0.300000 263.060000 16.000000 263.460000 ;
      RECT 0.000000 262.480000 16.000000 263.060000 ;
      RECT 0.300000 262.080000 16.000000 262.480000 ;
      RECT 0.000000 261.500000 16.000000 262.080000 ;
      RECT 0.300000 261.100000 16.000000 261.500000 ;
      RECT 0.000000 260.520000 16.000000 261.100000 ;
      RECT 0.300000 260.120000 16.000000 260.520000 ;
      RECT 0.000000 259.540000 16.000000 260.120000 ;
      RECT 0.300000 259.140000 16.000000 259.540000 ;
      RECT 0.000000 258.560000 16.000000 259.140000 ;
      RECT 0.300000 258.160000 16.000000 258.560000 ;
      RECT 0.000000 257.580000 16.000000 258.160000 ;
      RECT 0.300000 257.180000 16.000000 257.580000 ;
      RECT 0.000000 256.600000 16.000000 257.180000 ;
      RECT 0.300000 256.200000 16.000000 256.600000 ;
      RECT 0.000000 255.620000 16.000000 256.200000 ;
      RECT 0.300000 255.220000 16.000000 255.620000 ;
      RECT 0.000000 254.640000 16.000000 255.220000 ;
      RECT 0.300000 254.240000 16.000000 254.640000 ;
      RECT 0.000000 253.660000 16.000000 254.240000 ;
      RECT 0.300000 253.260000 16.000000 253.660000 ;
      RECT 0.000000 252.680000 16.000000 253.260000 ;
      RECT 0.300000 252.280000 16.000000 252.680000 ;
      RECT 0.000000 251.700000 16.000000 252.280000 ;
      RECT 0.300000 251.300000 16.000000 251.700000 ;
      RECT 0.000000 250.720000 16.000000 251.300000 ;
      RECT 0.300000 250.320000 16.000000 250.720000 ;
      RECT 0.000000 249.740000 16.000000 250.320000 ;
      RECT 0.300000 249.340000 16.000000 249.740000 ;
      RECT 0.000000 248.760000 16.000000 249.340000 ;
      RECT 0.300000 248.360000 16.000000 248.760000 ;
      RECT 0.000000 242.450000 16.000000 248.360000 ;
      RECT 0.300000 242.050000 16.000000 242.450000 ;
      RECT 0.000000 241.470000 16.000000 242.050000 ;
      RECT 0.300000 241.070000 16.000000 241.470000 ;
      RECT 0.000000 240.490000 16.000000 241.070000 ;
      RECT 0.300000 240.090000 16.000000 240.490000 ;
      RECT 0.000000 239.510000 16.000000 240.090000 ;
      RECT 0.300000 239.110000 16.000000 239.510000 ;
      RECT 0.000000 238.530000 16.000000 239.110000 ;
      RECT 0.300000 238.130000 16.000000 238.530000 ;
      RECT 0.000000 237.550000 16.000000 238.130000 ;
      RECT 0.300000 237.150000 16.000000 237.550000 ;
      RECT 0.000000 236.570000 16.000000 237.150000 ;
      RECT 0.300000 236.170000 16.000000 236.570000 ;
      RECT 0.000000 235.590000 16.000000 236.170000 ;
      RECT 0.300000 235.190000 16.000000 235.590000 ;
      RECT 0.000000 234.610000 16.000000 235.190000 ;
      RECT 0.300000 234.210000 16.000000 234.610000 ;
      RECT 0.000000 233.630000 16.000000 234.210000 ;
      RECT 0.300000 233.230000 16.000000 233.630000 ;
      RECT 0.000000 232.650000 16.000000 233.230000 ;
      RECT 0.300000 232.250000 16.000000 232.650000 ;
      RECT 0.000000 231.670000 16.000000 232.250000 ;
      RECT 0.300000 231.270000 16.000000 231.670000 ;
      RECT 0.000000 230.690000 16.000000 231.270000 ;
      RECT 0.300000 230.290000 16.000000 230.690000 ;
      RECT 0.000000 229.710000 16.000000 230.290000 ;
      RECT 0.300000 229.310000 16.000000 229.710000 ;
      RECT 0.000000 228.730000 16.000000 229.310000 ;
      RECT 0.300000 228.330000 16.000000 228.730000 ;
      RECT 0.000000 227.750000 16.000000 228.330000 ;
      RECT 0.300000 227.350000 16.000000 227.750000 ;
      RECT 0.000000 226.770000 16.000000 227.350000 ;
      RECT 0.300000 226.370000 16.000000 226.770000 ;
      RECT 0.000000 225.790000 16.000000 226.370000 ;
      RECT 0.300000 225.390000 16.000000 225.790000 ;
      RECT 0.000000 224.810000 16.000000 225.390000 ;
      RECT 0.300000 224.410000 16.000000 224.810000 ;
      RECT 0.000000 223.830000 16.000000 224.410000 ;
      RECT 0.300000 223.430000 16.000000 223.830000 ;
      RECT 0.000000 222.850000 16.000000 223.430000 ;
      RECT 0.300000 222.450000 16.000000 222.850000 ;
      RECT 0.000000 221.870000 16.000000 222.450000 ;
      RECT 0.300000 221.470000 16.000000 221.870000 ;
      RECT 0.000000 220.890000 16.000000 221.470000 ;
      RECT 0.300000 220.490000 16.000000 220.890000 ;
      RECT 0.000000 219.910000 16.000000 220.490000 ;
      RECT 0.300000 219.510000 16.000000 219.910000 ;
      RECT 0.000000 218.930000 16.000000 219.510000 ;
      RECT 0.300000 218.530000 16.000000 218.930000 ;
      RECT 0.000000 217.950000 16.000000 218.530000 ;
      RECT 0.300000 217.550000 16.000000 217.950000 ;
      RECT 0.000000 216.970000 16.000000 217.550000 ;
      RECT 0.300000 216.570000 16.000000 216.970000 ;
      RECT 0.000000 215.990000 16.000000 216.570000 ;
      RECT 0.300000 215.590000 16.000000 215.990000 ;
      RECT 0.000000 215.010000 16.000000 215.590000 ;
      RECT 0.300000 214.610000 16.000000 215.010000 ;
      RECT 0.000000 214.030000 16.000000 214.610000 ;
      RECT 0.300000 213.630000 16.000000 214.030000 ;
      RECT 0.000000 213.050000 16.000000 213.630000 ;
      RECT 0.300000 212.650000 16.000000 213.050000 ;
      RECT 0.000000 212.070000 16.000000 212.650000 ;
      RECT 0.300000 211.670000 16.000000 212.070000 ;
      RECT 0.000000 211.090000 16.000000 211.670000 ;
      RECT 0.300000 210.690000 16.000000 211.090000 ;
      RECT 0.000000 210.110000 16.000000 210.690000 ;
      RECT 0.300000 209.710000 16.000000 210.110000 ;
      RECT 0.000000 209.130000 16.000000 209.710000 ;
      RECT 0.300000 208.730000 16.000000 209.130000 ;
      RECT 0.000000 208.150000 16.000000 208.730000 ;
      RECT 0.300000 207.750000 16.000000 208.150000 ;
      RECT 0.000000 207.170000 16.000000 207.750000 ;
      RECT 0.300000 206.770000 16.000000 207.170000 ;
      RECT 0.000000 206.190000 16.000000 206.770000 ;
      RECT 0.300000 205.790000 16.000000 206.190000 ;
      RECT 0.000000 205.210000 16.000000 205.790000 ;
      RECT 0.300000 204.810000 16.000000 205.210000 ;
      RECT 0.000000 204.230000 16.000000 204.810000 ;
      RECT 0.300000 203.830000 16.000000 204.230000 ;
      RECT 0.000000 203.250000 16.000000 203.830000 ;
      RECT 0.300000 202.850000 16.000000 203.250000 ;
      RECT 0.000000 202.270000 16.000000 202.850000 ;
      RECT 0.300000 201.870000 16.000000 202.270000 ;
      RECT 0.000000 201.290000 16.000000 201.870000 ;
      RECT 0.300000 200.890000 16.000000 201.290000 ;
      RECT 0.000000 200.310000 16.000000 200.890000 ;
      RECT 0.300000 199.910000 16.000000 200.310000 ;
      RECT 0.000000 194.000000 16.000000 199.910000 ;
      RECT 0.300000 193.600000 16.000000 194.000000 ;
      RECT 0.000000 193.020000 16.000000 193.600000 ;
      RECT 0.300000 192.620000 16.000000 193.020000 ;
      RECT 0.000000 192.040000 16.000000 192.620000 ;
      RECT 0.300000 191.640000 16.000000 192.040000 ;
      RECT 0.000000 191.060000 16.000000 191.640000 ;
      RECT 0.300000 190.660000 16.000000 191.060000 ;
      RECT 0.000000 190.080000 16.000000 190.660000 ;
      RECT 0.300000 189.680000 16.000000 190.080000 ;
      RECT 0.000000 189.100000 16.000000 189.680000 ;
      RECT 0.300000 188.700000 16.000000 189.100000 ;
      RECT 0.000000 188.120000 16.000000 188.700000 ;
      RECT 0.300000 187.720000 16.000000 188.120000 ;
      RECT 0.000000 187.140000 16.000000 187.720000 ;
      RECT 0.300000 186.740000 16.000000 187.140000 ;
      RECT 0.000000 186.160000 16.000000 186.740000 ;
      RECT 0.300000 185.760000 16.000000 186.160000 ;
      RECT 0.000000 185.180000 16.000000 185.760000 ;
      RECT 0.300000 184.780000 16.000000 185.180000 ;
      RECT 0.000000 184.200000 16.000000 184.780000 ;
      RECT 0.300000 183.800000 16.000000 184.200000 ;
      RECT 0.000000 183.220000 16.000000 183.800000 ;
      RECT 0.300000 182.820000 16.000000 183.220000 ;
      RECT 0.000000 182.240000 16.000000 182.820000 ;
      RECT 0.300000 181.840000 16.000000 182.240000 ;
      RECT 0.000000 181.260000 16.000000 181.840000 ;
      RECT 0.300000 180.860000 16.000000 181.260000 ;
      RECT 0.000000 180.280000 16.000000 180.860000 ;
      RECT 0.300000 179.880000 16.000000 180.280000 ;
      RECT 0.000000 179.300000 16.000000 179.880000 ;
      RECT 0.300000 178.900000 16.000000 179.300000 ;
      RECT 0.000000 178.320000 16.000000 178.900000 ;
      RECT 0.300000 177.920000 16.000000 178.320000 ;
      RECT 0.000000 177.340000 16.000000 177.920000 ;
      RECT 0.300000 176.940000 16.000000 177.340000 ;
      RECT 0.000000 176.360000 16.000000 176.940000 ;
      RECT 0.300000 175.960000 16.000000 176.360000 ;
      RECT 0.000000 175.380000 16.000000 175.960000 ;
      RECT 0.300000 174.980000 16.000000 175.380000 ;
      RECT 0.000000 174.400000 16.000000 174.980000 ;
      RECT 0.300000 174.000000 16.000000 174.400000 ;
      RECT 0.000000 173.420000 16.000000 174.000000 ;
      RECT 0.300000 173.020000 16.000000 173.420000 ;
      RECT 0.000000 172.440000 16.000000 173.020000 ;
      RECT 0.300000 172.040000 16.000000 172.440000 ;
      RECT 0.000000 171.460000 16.000000 172.040000 ;
      RECT 0.300000 171.060000 16.000000 171.460000 ;
      RECT 0.000000 170.480000 16.000000 171.060000 ;
      RECT 0.300000 170.080000 16.000000 170.480000 ;
      RECT 0.000000 169.500000 16.000000 170.080000 ;
      RECT 0.300000 169.100000 16.000000 169.500000 ;
      RECT 0.000000 168.520000 16.000000 169.100000 ;
      RECT 0.300000 168.120000 16.000000 168.520000 ;
      RECT 0.000000 167.540000 16.000000 168.120000 ;
      RECT 0.300000 167.140000 16.000000 167.540000 ;
      RECT 0.000000 166.560000 16.000000 167.140000 ;
      RECT 0.300000 166.160000 16.000000 166.560000 ;
      RECT 0.000000 165.580000 16.000000 166.160000 ;
      RECT 0.300000 165.180000 16.000000 165.580000 ;
      RECT 0.000000 164.600000 16.000000 165.180000 ;
      RECT 0.300000 164.200000 16.000000 164.600000 ;
      RECT 0.000000 163.620000 16.000000 164.200000 ;
      RECT 0.300000 163.220000 16.000000 163.620000 ;
      RECT 0.000000 162.640000 16.000000 163.220000 ;
      RECT 0.300000 162.240000 16.000000 162.640000 ;
      RECT 0.000000 161.660000 16.000000 162.240000 ;
      RECT 0.300000 161.260000 16.000000 161.660000 ;
      RECT 0.000000 160.680000 16.000000 161.260000 ;
      RECT 0.300000 160.280000 16.000000 160.680000 ;
      RECT 0.000000 159.700000 16.000000 160.280000 ;
      RECT 0.300000 159.300000 16.000000 159.700000 ;
      RECT 0.000000 158.720000 16.000000 159.300000 ;
      RECT 0.300000 158.320000 16.000000 158.720000 ;
      RECT 0.000000 157.740000 16.000000 158.320000 ;
      RECT 0.300000 157.340000 16.000000 157.740000 ;
      RECT 0.000000 156.760000 16.000000 157.340000 ;
      RECT 0.300000 156.360000 16.000000 156.760000 ;
      RECT 0.000000 155.780000 16.000000 156.360000 ;
      RECT 0.300000 155.380000 16.000000 155.780000 ;
      RECT 0.000000 154.800000 16.000000 155.380000 ;
      RECT 0.300000 154.400000 16.000000 154.800000 ;
      RECT 0.000000 153.820000 16.000000 154.400000 ;
      RECT 0.300000 153.420000 16.000000 153.820000 ;
      RECT 0.000000 152.840000 16.000000 153.420000 ;
      RECT 0.300000 152.440000 16.000000 152.840000 ;
      RECT 0.000000 151.860000 16.000000 152.440000 ;
      RECT 0.300000 151.460000 16.000000 151.860000 ;
      RECT 0.000000 145.550000 16.000000 151.460000 ;
      RECT 0.300000 145.150000 16.000000 145.550000 ;
      RECT 0.000000 144.570000 16.000000 145.150000 ;
      RECT 0.300000 144.170000 16.000000 144.570000 ;
      RECT 0.000000 143.590000 16.000000 144.170000 ;
      RECT 0.300000 143.190000 16.000000 143.590000 ;
      RECT 0.000000 142.610000 16.000000 143.190000 ;
      RECT 0.300000 142.210000 16.000000 142.610000 ;
      RECT 0.000000 141.630000 16.000000 142.210000 ;
      RECT 0.300000 141.230000 16.000000 141.630000 ;
      RECT 0.000000 140.650000 16.000000 141.230000 ;
      RECT 0.300000 140.250000 16.000000 140.650000 ;
      RECT 0.000000 139.670000 16.000000 140.250000 ;
      RECT 0.300000 139.270000 16.000000 139.670000 ;
      RECT 0.000000 138.690000 16.000000 139.270000 ;
      RECT 0.300000 138.290000 16.000000 138.690000 ;
      RECT 0.000000 137.710000 16.000000 138.290000 ;
      RECT 0.300000 137.310000 16.000000 137.710000 ;
      RECT 0.000000 136.730000 16.000000 137.310000 ;
      RECT 0.300000 136.330000 16.000000 136.730000 ;
      RECT 0.000000 135.750000 16.000000 136.330000 ;
      RECT 0.300000 135.350000 16.000000 135.750000 ;
      RECT 0.000000 134.770000 16.000000 135.350000 ;
      RECT 0.300000 134.370000 16.000000 134.770000 ;
      RECT 0.000000 133.790000 16.000000 134.370000 ;
      RECT 0.300000 133.390000 16.000000 133.790000 ;
      RECT 0.000000 132.810000 16.000000 133.390000 ;
      RECT 0.300000 132.410000 16.000000 132.810000 ;
      RECT 0.000000 131.830000 16.000000 132.410000 ;
      RECT 0.300000 131.430000 16.000000 131.830000 ;
      RECT 0.000000 130.850000 16.000000 131.430000 ;
      RECT 0.300000 130.450000 16.000000 130.850000 ;
      RECT 0.000000 129.870000 16.000000 130.450000 ;
      RECT 0.300000 129.470000 16.000000 129.870000 ;
      RECT 0.000000 128.890000 16.000000 129.470000 ;
      RECT 0.300000 128.490000 16.000000 128.890000 ;
      RECT 0.000000 127.910000 16.000000 128.490000 ;
      RECT 0.300000 127.510000 16.000000 127.910000 ;
      RECT 0.000000 126.930000 16.000000 127.510000 ;
      RECT 0.300000 126.530000 16.000000 126.930000 ;
      RECT 0.000000 125.950000 16.000000 126.530000 ;
      RECT 0.300000 125.550000 16.000000 125.950000 ;
      RECT 0.000000 124.970000 16.000000 125.550000 ;
      RECT 0.300000 124.570000 16.000000 124.970000 ;
      RECT 0.000000 123.990000 16.000000 124.570000 ;
      RECT 0.300000 123.590000 16.000000 123.990000 ;
      RECT 0.000000 123.010000 16.000000 123.590000 ;
      RECT 0.300000 122.610000 16.000000 123.010000 ;
      RECT 0.000000 122.030000 16.000000 122.610000 ;
      RECT 0.300000 121.630000 16.000000 122.030000 ;
      RECT 0.000000 121.050000 16.000000 121.630000 ;
      RECT 0.300000 120.650000 16.000000 121.050000 ;
      RECT 0.000000 120.070000 16.000000 120.650000 ;
      RECT 0.300000 119.670000 16.000000 120.070000 ;
      RECT 0.000000 119.090000 16.000000 119.670000 ;
      RECT 0.300000 118.690000 16.000000 119.090000 ;
      RECT 0.000000 118.110000 16.000000 118.690000 ;
      RECT 0.300000 117.710000 16.000000 118.110000 ;
      RECT 0.000000 117.130000 16.000000 117.710000 ;
      RECT 0.300000 116.730000 16.000000 117.130000 ;
      RECT 0.000000 116.150000 16.000000 116.730000 ;
      RECT 0.300000 115.750000 16.000000 116.150000 ;
      RECT 0.000000 115.170000 16.000000 115.750000 ;
      RECT 0.300000 114.770000 16.000000 115.170000 ;
      RECT 0.000000 114.190000 16.000000 114.770000 ;
      RECT 0.300000 113.790000 16.000000 114.190000 ;
      RECT 0.000000 113.210000 16.000000 113.790000 ;
      RECT 0.300000 112.810000 16.000000 113.210000 ;
      RECT 0.000000 112.230000 16.000000 112.810000 ;
      RECT 0.300000 111.830000 16.000000 112.230000 ;
      RECT 0.000000 111.250000 16.000000 111.830000 ;
      RECT 0.300000 110.850000 16.000000 111.250000 ;
      RECT 0.000000 110.270000 16.000000 110.850000 ;
      RECT 0.300000 109.870000 16.000000 110.270000 ;
      RECT 0.000000 109.290000 16.000000 109.870000 ;
      RECT 0.300000 108.890000 16.000000 109.290000 ;
      RECT 0.000000 108.310000 16.000000 108.890000 ;
      RECT 0.300000 107.910000 16.000000 108.310000 ;
      RECT 0.000000 107.330000 16.000000 107.910000 ;
      RECT 0.300000 106.930000 16.000000 107.330000 ;
      RECT 0.000000 106.350000 16.000000 106.930000 ;
      RECT 0.300000 105.950000 16.000000 106.350000 ;
      RECT 0.000000 105.370000 16.000000 105.950000 ;
      RECT 0.300000 104.970000 16.000000 105.370000 ;
      RECT 0.000000 104.390000 16.000000 104.970000 ;
      RECT 0.300000 103.990000 16.000000 104.390000 ;
      RECT 0.000000 103.410000 16.000000 103.990000 ;
      RECT 0.300000 103.010000 16.000000 103.410000 ;
      RECT 0.000000 97.100000 16.000000 103.010000 ;
      RECT 0.300000 96.700000 16.000000 97.100000 ;
      RECT 0.000000 96.120000 16.000000 96.700000 ;
      RECT 0.300000 95.720000 16.000000 96.120000 ;
      RECT 0.000000 95.140000 16.000000 95.720000 ;
      RECT 0.300000 94.740000 16.000000 95.140000 ;
      RECT 0.000000 94.160000 16.000000 94.740000 ;
      RECT 0.300000 93.760000 16.000000 94.160000 ;
      RECT 0.000000 93.180000 16.000000 93.760000 ;
      RECT 0.300000 92.780000 16.000000 93.180000 ;
      RECT 0.000000 92.200000 16.000000 92.780000 ;
      RECT 0.300000 91.800000 16.000000 92.200000 ;
      RECT 0.000000 91.220000 16.000000 91.800000 ;
      RECT 0.300000 90.820000 16.000000 91.220000 ;
      RECT 0.000000 90.240000 16.000000 90.820000 ;
      RECT 0.300000 89.840000 16.000000 90.240000 ;
      RECT 0.000000 89.260000 16.000000 89.840000 ;
      RECT 0.300000 88.860000 16.000000 89.260000 ;
      RECT 0.000000 88.280000 16.000000 88.860000 ;
      RECT 0.300000 87.880000 16.000000 88.280000 ;
      RECT 0.000000 87.300000 16.000000 87.880000 ;
      RECT 0.300000 86.900000 16.000000 87.300000 ;
      RECT 0.000000 86.320000 16.000000 86.900000 ;
      RECT 0.300000 85.920000 16.000000 86.320000 ;
      RECT 0.000000 85.340000 16.000000 85.920000 ;
      RECT 0.300000 84.940000 16.000000 85.340000 ;
      RECT 0.000000 84.360000 16.000000 84.940000 ;
      RECT 0.300000 83.960000 16.000000 84.360000 ;
      RECT 0.000000 83.380000 16.000000 83.960000 ;
      RECT 0.300000 82.980000 16.000000 83.380000 ;
      RECT 0.000000 82.400000 16.000000 82.980000 ;
      RECT 0.300000 82.000000 16.000000 82.400000 ;
      RECT 0.000000 81.420000 16.000000 82.000000 ;
      RECT 0.300000 81.020000 16.000000 81.420000 ;
      RECT 0.000000 80.440000 16.000000 81.020000 ;
      RECT 0.300000 80.040000 16.000000 80.440000 ;
      RECT 0.000000 79.460000 16.000000 80.040000 ;
      RECT 0.300000 79.060000 16.000000 79.460000 ;
      RECT 0.000000 78.480000 16.000000 79.060000 ;
      RECT 0.300000 78.080000 16.000000 78.480000 ;
      RECT 0.000000 77.500000 16.000000 78.080000 ;
      RECT 0.300000 77.100000 16.000000 77.500000 ;
      RECT 0.000000 76.520000 16.000000 77.100000 ;
      RECT 0.300000 76.120000 16.000000 76.520000 ;
      RECT 0.000000 75.540000 16.000000 76.120000 ;
      RECT 0.300000 75.140000 16.000000 75.540000 ;
      RECT 0.000000 74.560000 16.000000 75.140000 ;
      RECT 0.300000 74.160000 16.000000 74.560000 ;
      RECT 0.000000 73.580000 16.000000 74.160000 ;
      RECT 0.300000 73.180000 16.000000 73.580000 ;
      RECT 0.000000 72.600000 16.000000 73.180000 ;
      RECT 0.300000 72.200000 16.000000 72.600000 ;
      RECT 0.000000 71.620000 16.000000 72.200000 ;
      RECT 0.300000 71.220000 16.000000 71.620000 ;
      RECT 0.000000 70.640000 16.000000 71.220000 ;
      RECT 0.300000 70.240000 16.000000 70.640000 ;
      RECT 0.000000 69.660000 16.000000 70.240000 ;
      RECT 0.300000 69.260000 16.000000 69.660000 ;
      RECT 0.000000 68.680000 16.000000 69.260000 ;
      RECT 0.300000 68.280000 16.000000 68.680000 ;
      RECT 0.000000 67.700000 16.000000 68.280000 ;
      RECT 0.300000 67.300000 16.000000 67.700000 ;
      RECT 0.000000 66.720000 16.000000 67.300000 ;
      RECT 0.300000 66.320000 16.000000 66.720000 ;
      RECT 0.000000 65.740000 16.000000 66.320000 ;
      RECT 0.300000 65.340000 16.000000 65.740000 ;
      RECT 0.000000 64.760000 16.000000 65.340000 ;
      RECT 0.300000 64.360000 16.000000 64.760000 ;
      RECT 0.000000 63.780000 16.000000 64.360000 ;
      RECT 0.300000 63.380000 16.000000 63.780000 ;
      RECT 0.000000 62.800000 16.000000 63.380000 ;
      RECT 0.300000 62.400000 16.000000 62.800000 ;
      RECT 0.000000 61.820000 16.000000 62.400000 ;
      RECT 0.300000 61.420000 16.000000 61.820000 ;
      RECT 0.000000 60.840000 16.000000 61.420000 ;
      RECT 0.300000 60.440000 16.000000 60.840000 ;
      RECT 0.000000 59.860000 16.000000 60.440000 ;
      RECT 0.300000 59.460000 16.000000 59.860000 ;
      RECT 0.000000 58.880000 16.000000 59.460000 ;
      RECT 0.300000 58.480000 16.000000 58.880000 ;
      RECT 0.000000 57.900000 16.000000 58.480000 ;
      RECT 0.300000 57.500000 16.000000 57.900000 ;
      RECT 0.000000 56.920000 16.000000 57.500000 ;
      RECT 0.300000 56.520000 16.000000 56.920000 ;
      RECT 0.000000 55.940000 16.000000 56.520000 ;
      RECT 0.300000 55.540000 16.000000 55.940000 ;
      RECT 0.000000 54.960000 16.000000 55.540000 ;
      RECT 0.300000 54.560000 16.000000 54.960000 ;
      RECT 0.000000 48.650000 16.000000 54.560000 ;
      RECT 0.300000 48.250000 16.000000 48.650000 ;
      RECT 0.000000 47.670000 16.000000 48.250000 ;
      RECT 0.300000 47.270000 16.000000 47.670000 ;
      RECT 0.000000 46.690000 16.000000 47.270000 ;
      RECT 0.300000 46.290000 16.000000 46.690000 ;
      RECT 0.000000 45.710000 16.000000 46.290000 ;
      RECT 0.300000 45.310000 16.000000 45.710000 ;
      RECT 0.000000 44.730000 16.000000 45.310000 ;
      RECT 0.300000 44.330000 16.000000 44.730000 ;
      RECT 0.000000 43.750000 16.000000 44.330000 ;
      RECT 0.300000 43.350000 16.000000 43.750000 ;
      RECT 0.000000 42.770000 16.000000 43.350000 ;
      RECT 0.300000 42.370000 16.000000 42.770000 ;
      RECT 0.000000 41.790000 16.000000 42.370000 ;
      RECT 0.300000 41.390000 16.000000 41.790000 ;
      RECT 0.000000 40.810000 16.000000 41.390000 ;
      RECT 0.300000 40.410000 16.000000 40.810000 ;
      RECT 0.000000 39.830000 16.000000 40.410000 ;
      RECT 0.300000 39.430000 16.000000 39.830000 ;
      RECT 0.000000 38.850000 16.000000 39.430000 ;
      RECT 0.300000 38.450000 16.000000 38.850000 ;
      RECT 0.000000 37.870000 16.000000 38.450000 ;
      RECT 0.300000 37.470000 16.000000 37.870000 ;
      RECT 0.000000 36.890000 16.000000 37.470000 ;
      RECT 0.300000 36.490000 16.000000 36.890000 ;
      RECT 0.000000 35.910000 16.000000 36.490000 ;
      RECT 0.300000 35.510000 16.000000 35.910000 ;
      RECT 0.000000 34.930000 16.000000 35.510000 ;
      RECT 0.300000 34.530000 16.000000 34.930000 ;
      RECT 0.000000 33.950000 16.000000 34.530000 ;
      RECT 0.300000 33.550000 16.000000 33.950000 ;
      RECT 0.000000 32.970000 16.000000 33.550000 ;
      RECT 0.300000 32.570000 16.000000 32.970000 ;
      RECT 0.000000 31.990000 16.000000 32.570000 ;
      RECT 0.300000 31.590000 16.000000 31.990000 ;
      RECT 0.000000 31.010000 16.000000 31.590000 ;
      RECT 0.300000 30.610000 16.000000 31.010000 ;
      RECT 0.000000 30.030000 16.000000 30.610000 ;
      RECT 0.300000 29.630000 16.000000 30.030000 ;
      RECT 0.000000 29.050000 16.000000 29.630000 ;
      RECT 0.300000 28.650000 16.000000 29.050000 ;
      RECT 0.000000 28.070000 16.000000 28.650000 ;
      RECT 0.300000 27.670000 16.000000 28.070000 ;
      RECT 0.000000 27.090000 16.000000 27.670000 ;
      RECT 0.300000 26.690000 16.000000 27.090000 ;
      RECT 0.000000 26.110000 16.000000 26.690000 ;
      RECT 0.300000 25.710000 16.000000 26.110000 ;
      RECT 0.000000 25.130000 16.000000 25.710000 ;
      RECT 0.300000 24.730000 16.000000 25.130000 ;
      RECT 0.000000 24.150000 16.000000 24.730000 ;
      RECT 0.300000 23.750000 16.000000 24.150000 ;
      RECT 0.000000 23.170000 16.000000 23.750000 ;
      RECT 0.300000 22.770000 16.000000 23.170000 ;
      RECT 0.000000 22.190000 16.000000 22.770000 ;
      RECT 0.300000 21.790000 16.000000 22.190000 ;
      RECT 0.000000 21.210000 16.000000 21.790000 ;
      RECT 0.300000 20.810000 16.000000 21.210000 ;
      RECT 0.000000 20.230000 16.000000 20.810000 ;
      RECT 0.300000 19.830000 16.000000 20.230000 ;
      RECT 0.000000 19.250000 16.000000 19.830000 ;
      RECT 0.300000 18.850000 16.000000 19.250000 ;
      RECT 0.000000 18.270000 16.000000 18.850000 ;
      RECT 0.300000 17.870000 16.000000 18.270000 ;
      RECT 0.000000 17.290000 16.000000 17.870000 ;
      RECT 0.300000 16.890000 16.000000 17.290000 ;
      RECT 0.000000 16.310000 16.000000 16.890000 ;
      RECT 0.300000 15.910000 16.000000 16.310000 ;
      RECT 0.000000 15.330000 16.000000 15.910000 ;
      RECT 0.300000 14.930000 16.000000 15.330000 ;
      RECT 0.000000 14.350000 16.000000 14.930000 ;
      RECT 0.300000 13.950000 16.000000 14.350000 ;
      RECT 0.000000 13.370000 16.000000 13.950000 ;
      RECT 0.300000 12.970000 16.000000 13.370000 ;
      RECT 0.000000 12.390000 16.000000 12.970000 ;
      RECT 0.300000 11.990000 16.000000 12.390000 ;
      RECT 0.000000 11.410000 16.000000 11.990000 ;
      RECT 0.300000 11.010000 16.000000 11.410000 ;
      RECT 0.000000 10.430000 16.000000 11.010000 ;
      RECT 0.300000 10.030000 16.000000 10.430000 ;
      RECT 0.000000 9.450000 16.000000 10.030000 ;
      RECT 0.300000 9.050000 16.000000 9.450000 ;
      RECT 0.000000 8.470000 16.000000 9.050000 ;
      RECT 0.300000 8.070000 16.000000 8.470000 ;
      RECT 0.000000 7.490000 16.000000 8.070000 ;
      RECT 0.300000 7.090000 16.000000 7.490000 ;
      RECT 0.000000 6.510000 16.000000 7.090000 ;
      RECT 0.300000 6.110000 16.000000 6.510000 ;
      RECT 0.000000 0.000000 16.000000 6.110000 ;
  END
END local_ctrl_row

END LIBRARY
